VERSION 5.7 ;
  NOWIREEXTENSIONATPIN ON ;
  DIVIDERCHAR "/" ;
  BUSBITCHARS "[]" ;
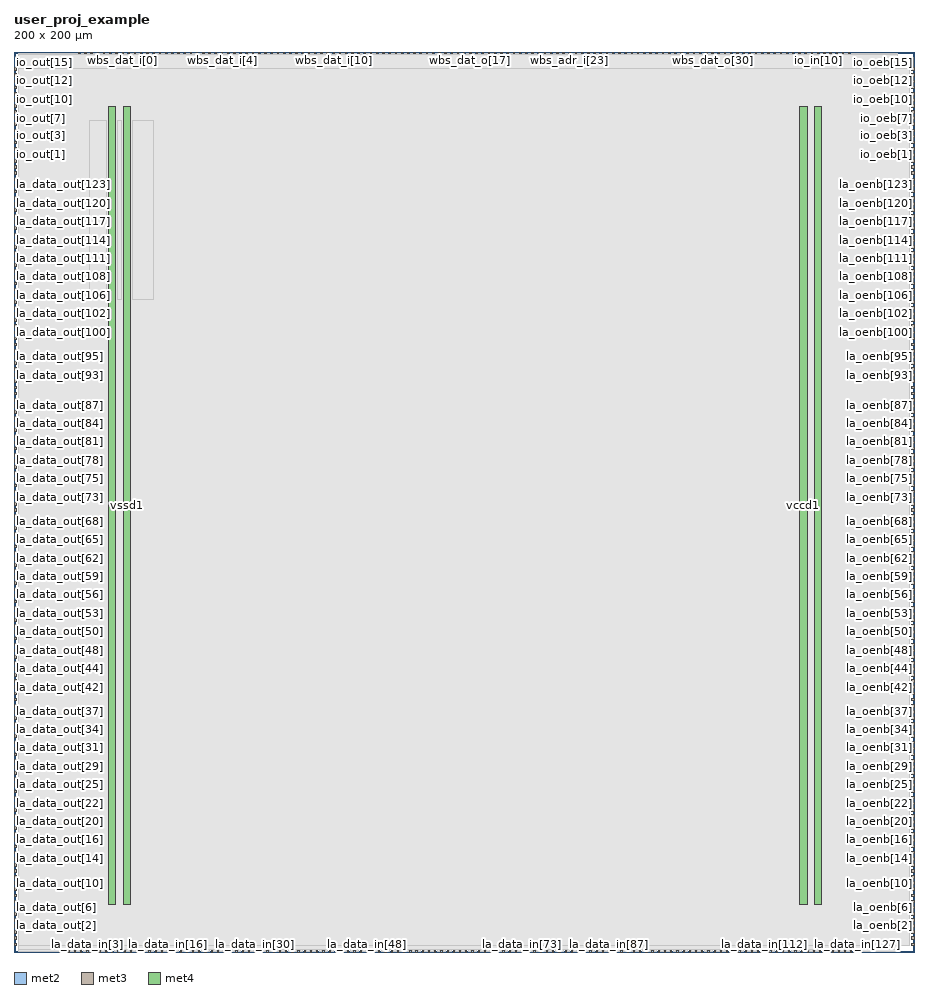
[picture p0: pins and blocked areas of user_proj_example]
MACRO user_proj_example
  CLASS BLOCK ;
  FOREIGN user_proj_example ;
  ORIGIN 0.000 0.000 ;
  SIZE 200.000 BY 200.000 ;
  PIN io_in[0]
    DIRECTION INPUT ;
    USE SIGNAL ;
    PORT
      LAYER met2 ;
        RECT 164.770 199.720 165.050 200.000 ;
    END
  END io_in[0]
  PIN io_in[10]
    DIRECTION INPUT ;
    USE SIGNAL ;
    PORT
      LAYER met2 ;
        RECT 178.570 199.720 178.850 200.000 ;
    END
  END io_in[10]
  PIN io_in[11]
    DIRECTION INPUT ;
    USE SIGNAL ;
    PORT
      LAYER met2 ;
        RECT 179.950 199.720 180.230 200.000 ;
    END
  END io_in[11]
  PIN io_in[12]
    DIRECTION INPUT ;
    USE SIGNAL ;
    PORT
      LAYER met2 ;
        RECT 181.330 199.720 181.610 200.000 ;
    END
  END io_in[12]
  PIN io_in[13]
    DIRECTION INPUT ;
    USE SIGNAL ;
    PORT
      LAYER met2 ;
        RECT 182.710 199.720 182.990 200.000 ;
    END
  END io_in[13]
  PIN io_in[14]
    DIRECTION INPUT ;
    USE SIGNAL ;
    PORT
      LAYER met2 ;
        RECT 184.090 199.720 184.370 200.000 ;
    END
  END io_in[14]
  PIN io_in[15]
    DIRECTION INPUT ;
    USE SIGNAL ;
    PORT
      LAYER met2 ;
        RECT 185.470 199.720 185.750 200.000 ;
    END
  END io_in[15]
  PIN io_in[1]
    DIRECTION INPUT ;
    USE SIGNAL ;
    PORT
      LAYER met2 ;
        RECT 166.150 199.720 166.430 200.000 ;
    END
  END io_in[1]
  PIN io_in[2]
    DIRECTION INPUT ;
    USE SIGNAL ;
    PORT
      LAYER met2 ;
        RECT 167.530 199.720 167.810 200.000 ;
    END
  END io_in[2]
  PIN io_in[3]
    DIRECTION INPUT ;
    USE SIGNAL ;
    PORT
      LAYER met2 ;
        RECT 168.910 199.720 169.190 200.000 ;
    END
  END io_in[3]
  PIN io_in[4]
    DIRECTION INPUT ;
    USE SIGNAL ;
    PORT
      LAYER met2 ;
        RECT 170.290 199.720 170.570 200.000 ;
    END
  END io_in[4]
  PIN io_in[5]
    DIRECTION INPUT ;
    USE SIGNAL ;
    PORT
      LAYER met2 ;
        RECT 171.670 199.720 171.950 200.000 ;
    END
  END io_in[5]
  PIN io_in[6]
    DIRECTION INPUT ;
    USE SIGNAL ;
    PORT
      LAYER met2 ;
        RECT 173.050 199.720 173.330 200.000 ;
    END
  END io_in[6]
  PIN io_in[7]
    DIRECTION INPUT ;
    USE SIGNAL ;
    PORT
      LAYER met2 ;
        RECT 174.430 199.720 174.710 200.000 ;
    END
  END io_in[7]
  PIN io_in[8]
    DIRECTION INPUT ;
    USE SIGNAL ;
    PORT
      LAYER met2 ;
        RECT 175.810 199.720 176.090 200.000 ;
    END
  END io_in[8]
  PIN io_in[9]
    DIRECTION INPUT ;
    USE SIGNAL ;
    PORT
      LAYER met2 ;
        RECT 177.190 199.720 177.470 200.000 ;
    END
  END io_in[9]
  PIN io_oeb[0]
    DIRECTION OUTPUT ;
    USE SIGNAL ;
    ANTENNADIFFAREA 2.673000 ;
    PORT
      LAYER met3 ;
        RECT 199.400 175.480 200.000 176.080 ;
    END
  END io_oeb[0]
  PIN io_oeb[10]
    DIRECTION OUTPUT ;
    USE SIGNAL ;
    ANTENNADIFFAREA 2.673000 ;
    PORT
      LAYER met3 ;
        RECT 199.400 189.080 200.000 189.680 ;
    END
  END io_oeb[10]
  PIN io_oeb[11]
    DIRECTION OUTPUT ;
    USE SIGNAL ;
    ANTENNADIFFAREA 2.673000 ;
    PORT
      LAYER met3 ;
        RECT 199.400 190.440 200.000 191.040 ;
    END
  END io_oeb[11]
  PIN io_oeb[12]
    DIRECTION OUTPUT ;
    USE SIGNAL ;
    ANTENNADIFFAREA 2.673000 ;
    PORT
      LAYER met3 ;
        RECT 199.400 191.800 200.000 192.400 ;
    END
  END io_oeb[12]
  PIN io_oeb[13]
    DIRECTION OUTPUT ;
    USE SIGNAL ;
    ANTENNADIFFAREA 2.673000 ;
    PORT
      LAYER met3 ;
        RECT 199.400 193.160 200.000 193.760 ;
    END
  END io_oeb[13]
  PIN io_oeb[14]
    DIRECTION OUTPUT ;
    USE SIGNAL ;
    ANTENNADIFFAREA 2.673000 ;
    PORT
      LAYER met3 ;
        RECT 199.400 194.520 200.000 195.120 ;
    END
  END io_oeb[14]
  PIN io_oeb[15]
    DIRECTION OUTPUT ;
    USE SIGNAL ;
    ANTENNADIFFAREA 2.673000 ;
    PORT
      LAYER met3 ;
        RECT 199.400 195.880 200.000 196.480 ;
    END
  END io_oeb[15]
  PIN io_oeb[1]
    DIRECTION OUTPUT ;
    USE SIGNAL ;
    ANTENNADIFFAREA 2.673000 ;
    PORT
      LAYER met3 ;
        RECT 199.400 176.840 200.000 177.440 ;
    END
  END io_oeb[1]
  PIN io_oeb[2]
    DIRECTION OUTPUT ;
    USE SIGNAL ;
    ANTENNADIFFAREA 2.673000 ;
    PORT
      LAYER met3 ;
        RECT 199.400 178.200 200.000 178.800 ;
    END
  END io_oeb[2]
  PIN io_oeb[3]
    DIRECTION OUTPUT ;
    USE SIGNAL ;
    ANTENNADIFFAREA 2.673000 ;
    PORT
      LAYER met3 ;
        RECT 199.400 179.560 200.000 180.160 ;
    END
  END io_oeb[3]
  PIN io_oeb[4]
    DIRECTION OUTPUT ;
    USE SIGNAL ;
    ANTENNADIFFAREA 2.673000 ;
    PORT
      LAYER met3 ;
        RECT 199.400 180.920 200.000 181.520 ;
    END
  END io_oeb[4]
  PIN io_oeb[5]
    DIRECTION OUTPUT ;
    USE SIGNAL ;
    ANTENNADIFFAREA 2.673000 ;
    PORT
      LAYER met3 ;
        RECT 199.400 182.280 200.000 182.880 ;
    END
  END io_oeb[5]
  PIN io_oeb[6]
    DIRECTION OUTPUT ;
    USE SIGNAL ;
    ANTENNADIFFAREA 2.673000 ;
    PORT
      LAYER met3 ;
        RECT 199.400 183.640 200.000 184.240 ;
    END
  END io_oeb[6]
  PIN io_oeb[7]
    DIRECTION OUTPUT ;
    USE SIGNAL ;
    ANTENNADIFFAREA 2.673000 ;
    PORT
      LAYER met3 ;
        RECT 199.400 185.000 200.000 185.600 ;
    END
  END io_oeb[7]
  PIN io_oeb[8]
    DIRECTION OUTPUT ;
    USE SIGNAL ;
    ANTENNADIFFAREA 2.673000 ;
    PORT
      LAYER met3 ;
        RECT 199.400 186.360 200.000 186.960 ;
    END
  END io_oeb[8]
  PIN io_oeb[9]
    DIRECTION OUTPUT ;
    USE SIGNAL ;
    ANTENNADIFFAREA 2.673000 ;
    PORT
      LAYER met3 ;
        RECT 199.400 187.720 200.000 188.320 ;
    END
  END io_oeb[9]
  PIN io_out[0]
    DIRECTION OUTPUT ;
    USE SIGNAL ;
    ANTENNADIFFAREA 2.673000 ;
    PORT
      LAYER met3 ;
        RECT 0.000 175.480 0.600 176.080 ;
    END
  END io_out[0]
  PIN io_out[10]
    DIRECTION OUTPUT ;
    USE SIGNAL ;
    ANTENNADIFFAREA 2.673000 ;
    PORT
      LAYER met3 ;
        RECT 0.000 189.080 0.600 189.680 ;
    END
  END io_out[10]
  PIN io_out[11]
    DIRECTION OUTPUT ;
    USE SIGNAL ;
    ANTENNADIFFAREA 2.673000 ;
    PORT
      LAYER met3 ;
        RECT 0.000 190.440 0.600 191.040 ;
    END
  END io_out[11]
  PIN io_out[12]
    DIRECTION OUTPUT ;
    USE SIGNAL ;
    ANTENNADIFFAREA 2.673000 ;
    PORT
      LAYER met3 ;
        RECT 0.000 191.800 0.600 192.400 ;
    END
  END io_out[12]
  PIN io_out[13]
    DIRECTION OUTPUT ;
    USE SIGNAL ;
    ANTENNADIFFAREA 2.673000 ;
    PORT
      LAYER met3 ;
        RECT 0.000 193.160 0.600 193.760 ;
    END
  END io_out[13]
  PIN io_out[14]
    DIRECTION OUTPUT ;
    USE SIGNAL ;
    ANTENNADIFFAREA 2.673000 ;
    PORT
      LAYER met3 ;
        RECT 0.000 194.520 0.600 195.120 ;
    END
  END io_out[14]
  PIN io_out[15]
    DIRECTION OUTPUT ;
    USE SIGNAL ;
    ANTENNADIFFAREA 2.673000 ;
    PORT
      LAYER met3 ;
        RECT 0.000 195.880 0.600 196.480 ;
    END
  END io_out[15]
  PIN io_out[1]
    DIRECTION OUTPUT ;
    USE SIGNAL ;
    ANTENNADIFFAREA 2.673000 ;
    PORT
      LAYER met3 ;
        RECT 0.000 176.840 0.600 177.440 ;
    END
  END io_out[1]
  PIN io_out[2]
    DIRECTION OUTPUT ;
    USE SIGNAL ;
    ANTENNADIFFAREA 2.673000 ;
    PORT
      LAYER met3 ;
        RECT 0.000 178.200 0.600 178.800 ;
    END
  END io_out[2]
  PIN io_out[3]
    DIRECTION OUTPUT ;
    USE SIGNAL ;
    ANTENNADIFFAREA 2.673000 ;
    PORT
      LAYER met3 ;
        RECT 0.000 179.560 0.600 180.160 ;
    END
  END io_out[3]
  PIN io_out[4]
    DIRECTION OUTPUT ;
    USE SIGNAL ;
    ANTENNADIFFAREA 2.673000 ;
    PORT
      LAYER met3 ;
        RECT 0.000 180.920 0.600 181.520 ;
    END
  END io_out[4]
  PIN io_out[5]
    DIRECTION OUTPUT ;
    USE SIGNAL ;
    ANTENNADIFFAREA 2.673000 ;
    PORT
      LAYER met3 ;
        RECT 0.000 182.280 0.600 182.880 ;
    END
  END io_out[5]
  PIN io_out[6]
    DIRECTION OUTPUT ;
    USE SIGNAL ;
    ANTENNADIFFAREA 2.673000 ;
    PORT
      LAYER met3 ;
        RECT 0.000 183.640 0.600 184.240 ;
    END
  END io_out[6]
  PIN io_out[7]
    DIRECTION OUTPUT ;
    USE SIGNAL ;
    ANTENNADIFFAREA 2.673000 ;
    PORT
      LAYER met3 ;
        RECT 0.000 185.000 0.600 185.600 ;
    END
  END io_out[7]
  PIN io_out[8]
    DIRECTION OUTPUT ;
    USE SIGNAL ;
    ANTENNADIFFAREA 2.673000 ;
    PORT
      LAYER met3 ;
        RECT 0.000 186.360 0.600 186.960 ;
    END
  END io_out[8]
  PIN io_out[9]
    DIRECTION OUTPUT ;
    USE SIGNAL ;
    ANTENNADIFFAREA 2.673000 ;
    PORT
      LAYER met3 ;
        RECT 0.000 187.720 0.600 188.320 ;
    END
  END io_out[9]
  PIN irq[0]
    DIRECTION OUTPUT ;
    USE SIGNAL ;
    PORT
      LAYER met2 ;
        RECT 160.630 199.720 160.910 200.000 ;
    END
  END irq[0]
  PIN irq[1]
    DIRECTION OUTPUT ;
    USE SIGNAL ;
    PORT
      LAYER met2 ;
        RECT 162.010 199.720 162.290 200.000 ;
    END
  END irq[1]
  PIN irq[2]
    DIRECTION OUTPUT ;
    USE SIGNAL ;
    PORT
      LAYER met2 ;
        RECT 163.390 199.720 163.670 200.000 ;
    END
  END irq[2]
  PIN la_data_in[0]
    DIRECTION INPUT ;
    USE SIGNAL ;
    PORT
      LAYER met2 ;
        RECT 12.050 0.000 12.330 0.280 ;
    END
  END la_data_in[0]
  PIN la_data_in[100]
    DIRECTION INPUT ;
    USE SIGNAL ;
    PORT
      LAYER met2 ;
        RECT 150.050 0.000 150.330 0.280 ;
    END
  END la_data_in[100]
  PIN la_data_in[101]
    DIRECTION INPUT ;
    USE SIGNAL ;
    PORT
      LAYER met2 ;
        RECT 151.430 0.000 151.710 0.280 ;
    END
  END la_data_in[101]
  PIN la_data_in[102]
    DIRECTION INPUT ;
    USE SIGNAL ;
    PORT
      LAYER met2 ;
        RECT 152.810 0.000 153.090 0.280 ;
    END
  END la_data_in[102]
  PIN la_data_in[103]
    DIRECTION INPUT ;
    USE SIGNAL ;
    PORT
      LAYER met2 ;
        RECT 154.190 0.000 154.470 0.280 ;
    END
  END la_data_in[103]
  PIN la_data_in[104]
    DIRECTION INPUT ;
    USE SIGNAL ;
    PORT
      LAYER met2 ;
        RECT 155.570 0.000 155.850 0.280 ;
    END
  END la_data_in[104]
  PIN la_data_in[105]
    DIRECTION INPUT ;
    USE SIGNAL ;
    PORT
      LAYER met2 ;
        RECT 156.950 0.000 157.230 0.280 ;
    END
  END la_data_in[105]
  PIN la_data_in[106]
    DIRECTION INPUT ;
    USE SIGNAL ;
    PORT
      LAYER met2 ;
        RECT 158.330 0.000 158.610 0.280 ;
    END
  END la_data_in[106]
  PIN la_data_in[107]
    DIRECTION INPUT ;
    USE SIGNAL ;
    PORT
      LAYER met2 ;
        RECT 159.710 0.000 159.990 0.280 ;
    END
  END la_data_in[107]
  PIN la_data_in[108]
    DIRECTION INPUT ;
    USE SIGNAL ;
    PORT
      LAYER met2 ;
        RECT 161.090 0.000 161.370 0.280 ;
    END
  END la_data_in[108]
  PIN la_data_in[109]
    DIRECTION INPUT ;
    USE SIGNAL ;
    PORT
      LAYER met2 ;
        RECT 162.470 0.000 162.750 0.280 ;
    END
  END la_data_in[109]
  PIN la_data_in[10]
    DIRECTION INPUT ;
    USE SIGNAL ;
    PORT
      LAYER met2 ;
        RECT 25.850 0.000 26.130 0.280 ;
    END
  END la_data_in[10]
  PIN la_data_in[110]
    DIRECTION INPUT ;
    USE SIGNAL ;
    PORT
      LAYER met2 ;
        RECT 163.850 0.000 164.130 0.280 ;
    END
  END la_data_in[110]
  PIN la_data_in[111]
    DIRECTION INPUT ;
    USE SIGNAL ;
    PORT
      LAYER met2 ;
        RECT 165.230 0.000 165.510 0.280 ;
    END
  END la_data_in[111]
  PIN la_data_in[112]
    DIRECTION INPUT ;
    USE SIGNAL ;
    PORT
      LAYER met2 ;
        RECT 166.610 0.000 166.890 0.280 ;
    END
  END la_data_in[112]
  PIN la_data_in[113]
    DIRECTION INPUT ;
    USE SIGNAL ;
    PORT
      LAYER met2 ;
        RECT 167.990 0.000 168.270 0.280 ;
    END
  END la_data_in[113]
  PIN la_data_in[114]
    DIRECTION INPUT ;
    USE SIGNAL ;
    PORT
      LAYER met2 ;
        RECT 169.370 0.000 169.650 0.280 ;
    END
  END la_data_in[114]
  PIN la_data_in[115]
    DIRECTION INPUT ;
    USE SIGNAL ;
    PORT
      LAYER met2 ;
        RECT 170.750 0.000 171.030 0.280 ;
    END
  END la_data_in[115]
  PIN la_data_in[116]
    DIRECTION INPUT ;
    USE SIGNAL ;
    PORT
      LAYER met2 ;
        RECT 172.130 0.000 172.410 0.280 ;
    END
  END la_data_in[116]
  PIN la_data_in[117]
    DIRECTION INPUT ;
    USE SIGNAL ;
    PORT
      LAYER met2 ;
        RECT 173.510 0.000 173.790 0.280 ;
    END
  END la_data_in[117]
  PIN la_data_in[118]
    DIRECTION INPUT ;
    USE SIGNAL ;
    PORT
      LAYER met2 ;
        RECT 174.890 0.000 175.170 0.280 ;
    END
  END la_data_in[118]
  PIN la_data_in[119]
    DIRECTION INPUT ;
    USE SIGNAL ;
    PORT
      LAYER met2 ;
        RECT 176.270 0.000 176.550 0.280 ;
    END
  END la_data_in[119]
  PIN la_data_in[11]
    DIRECTION INPUT ;
    USE SIGNAL ;
    PORT
      LAYER met2 ;
        RECT 27.230 0.000 27.510 0.280 ;
    END
  END la_data_in[11]
  PIN la_data_in[120]
    DIRECTION INPUT ;
    USE SIGNAL ;
    PORT
      LAYER met2 ;
        RECT 177.650 0.000 177.930 0.280 ;
    END
  END la_data_in[120]
  PIN la_data_in[121]
    DIRECTION INPUT ;
    USE SIGNAL ;
    PORT
      LAYER met2 ;
        RECT 179.030 0.000 179.310 0.280 ;
    END
  END la_data_in[121]
  PIN la_data_in[122]
    DIRECTION INPUT ;
    USE SIGNAL ;
    PORT
      LAYER met2 ;
        RECT 180.410 0.000 180.690 0.280 ;
    END
  END la_data_in[122]
  PIN la_data_in[123]
    DIRECTION INPUT ;
    USE SIGNAL ;
    PORT
      LAYER met2 ;
        RECT 181.790 0.000 182.070 0.280 ;
    END
  END la_data_in[123]
  PIN la_data_in[124]
    DIRECTION INPUT ;
    USE SIGNAL ;
    PORT
      LAYER met2 ;
        RECT 183.170 0.000 183.450 0.280 ;
    END
  END la_data_in[124]
  PIN la_data_in[125]
    DIRECTION INPUT ;
    USE SIGNAL ;
    PORT
      LAYER met2 ;
        RECT 184.550 0.000 184.830 0.280 ;
    END
  END la_data_in[125]
  PIN la_data_in[126]
    DIRECTION INPUT ;
    USE SIGNAL ;
    PORT
      LAYER met2 ;
        RECT 185.930 0.000 186.210 0.280 ;
    END
  END la_data_in[126]
  PIN la_data_in[127]
    DIRECTION INPUT ;
    USE SIGNAL ;
    PORT
      LAYER met2 ;
        RECT 187.310 0.000 187.590 0.280 ;
    END
  END la_data_in[127]
  PIN la_data_in[12]
    DIRECTION INPUT ;
    USE SIGNAL ;
    PORT
      LAYER met2 ;
        RECT 28.610 0.000 28.890 0.280 ;
    END
  END la_data_in[12]
  PIN la_data_in[13]
    DIRECTION INPUT ;
    USE SIGNAL ;
    PORT
      LAYER met2 ;
        RECT 29.990 0.000 30.270 0.280 ;
    END
  END la_data_in[13]
  PIN la_data_in[14]
    DIRECTION INPUT ;
    USE SIGNAL ;
    PORT
      LAYER met2 ;
        RECT 31.370 0.000 31.650 0.280 ;
    END
  END la_data_in[14]
  PIN la_data_in[15]
    DIRECTION INPUT ;
    USE SIGNAL ;
    PORT
      LAYER met2 ;
        RECT 32.750 0.000 33.030 0.280 ;
    END
  END la_data_in[15]
  PIN la_data_in[16]
    DIRECTION INPUT ;
    USE SIGNAL ;
    PORT
      LAYER met2 ;
        RECT 34.130 0.000 34.410 0.280 ;
    END
  END la_data_in[16]
  PIN la_data_in[17]
    DIRECTION INPUT ;
    USE SIGNAL ;
    PORT
      LAYER met2 ;
        RECT 35.510 0.000 35.790 0.280 ;
    END
  END la_data_in[17]
  PIN la_data_in[18]
    DIRECTION INPUT ;
    USE SIGNAL ;
    PORT
      LAYER met2 ;
        RECT 36.890 0.000 37.170 0.280 ;
    END
  END la_data_in[18]
  PIN la_data_in[19]
    DIRECTION INPUT ;
    USE SIGNAL ;
    PORT
      LAYER met2 ;
        RECT 38.270 0.000 38.550 0.280 ;
    END
  END la_data_in[19]
  PIN la_data_in[1]
    DIRECTION INPUT ;
    USE SIGNAL ;
    PORT
      LAYER met2 ;
        RECT 13.430 0.000 13.710 0.280 ;
    END
  END la_data_in[1]
  PIN la_data_in[20]
    DIRECTION INPUT ;
    USE SIGNAL ;
    PORT
      LAYER met2 ;
        RECT 39.650 0.000 39.930 0.280 ;
    END
  END la_data_in[20]
  PIN la_data_in[21]
    DIRECTION INPUT ;
    USE SIGNAL ;
    PORT
      LAYER met2 ;
        RECT 41.030 0.000 41.310 0.280 ;
    END
  END la_data_in[21]
  PIN la_data_in[22]
    DIRECTION INPUT ;
    USE SIGNAL ;
    PORT
      LAYER met2 ;
        RECT 42.410 0.000 42.690 0.280 ;
    END
  END la_data_in[22]
  PIN la_data_in[23]
    DIRECTION INPUT ;
    USE SIGNAL ;
    PORT
      LAYER met2 ;
        RECT 43.790 0.000 44.070 0.280 ;
    END
  END la_data_in[23]
  PIN la_data_in[24]
    DIRECTION INPUT ;
    USE SIGNAL ;
    PORT
      LAYER met2 ;
        RECT 45.170 0.000 45.450 0.280 ;
    END
  END la_data_in[24]
  PIN la_data_in[25]
    DIRECTION INPUT ;
    USE SIGNAL ;
    PORT
      LAYER met2 ;
        RECT 46.550 0.000 46.830 0.280 ;
    END
  END la_data_in[25]
  PIN la_data_in[26]
    DIRECTION INPUT ;
    USE SIGNAL ;
    PORT
      LAYER met2 ;
        RECT 47.930 0.000 48.210 0.280 ;
    END
  END la_data_in[26]
  PIN la_data_in[27]
    DIRECTION INPUT ;
    USE SIGNAL ;
    PORT
      LAYER met2 ;
        RECT 49.310 0.000 49.590 0.280 ;
    END
  END la_data_in[27]
  PIN la_data_in[28]
    DIRECTION INPUT ;
    USE SIGNAL ;
    PORT
      LAYER met2 ;
        RECT 50.690 0.000 50.970 0.280 ;
    END
  END la_data_in[28]
  PIN la_data_in[29]
    DIRECTION INPUT ;
    USE SIGNAL ;
    PORT
      LAYER met2 ;
        RECT 52.070 0.000 52.350 0.280 ;
    END
  END la_data_in[29]
  PIN la_data_in[2]
    DIRECTION INPUT ;
    USE SIGNAL ;
    PORT
      LAYER met2 ;
        RECT 14.810 0.000 15.090 0.280 ;
    END
  END la_data_in[2]
  PIN la_data_in[30]
    DIRECTION INPUT ;
    USE SIGNAL ;
    PORT
      LAYER met2 ;
        RECT 53.450 0.000 53.730 0.280 ;
    END
  END la_data_in[30]
  PIN la_data_in[31]
    DIRECTION INPUT ;
    USE SIGNAL ;
    PORT
      LAYER met2 ;
        RECT 54.830 0.000 55.110 0.280 ;
    END
  END la_data_in[31]
  PIN la_data_in[32]
    DIRECTION INPUT ;
    USE SIGNAL ;
    PORT
      LAYER met2 ;
        RECT 56.210 0.000 56.490 0.280 ;
    END
  END la_data_in[32]
  PIN la_data_in[33]
    DIRECTION INPUT ;
    USE SIGNAL ;
    PORT
      LAYER met2 ;
        RECT 57.590 0.000 57.870 0.280 ;
    END
  END la_data_in[33]
  PIN la_data_in[34]
    DIRECTION INPUT ;
    USE SIGNAL ;
    PORT
      LAYER met2 ;
        RECT 58.970 0.000 59.250 0.280 ;
    END
  END la_data_in[34]
  PIN la_data_in[35]
    DIRECTION INPUT ;
    USE SIGNAL ;
    PORT
      LAYER met2 ;
        RECT 60.350 0.000 60.630 0.280 ;
    END
  END la_data_in[35]
  PIN la_data_in[36]
    DIRECTION INPUT ;
    USE SIGNAL ;
    PORT
      LAYER met2 ;
        RECT 61.730 0.000 62.010 0.280 ;
    END
  END la_data_in[36]
  PIN la_data_in[37]
    DIRECTION INPUT ;
    USE SIGNAL ;
    PORT
      LAYER met2 ;
        RECT 63.110 0.000 63.390 0.280 ;
    END
  END la_data_in[37]
  PIN la_data_in[38]
    DIRECTION INPUT ;
    USE SIGNAL ;
    PORT
      LAYER met2 ;
        RECT 64.490 0.000 64.770 0.280 ;
    END
  END la_data_in[38]
  PIN la_data_in[39]
    DIRECTION INPUT ;
    USE SIGNAL ;
    PORT
      LAYER met2 ;
        RECT 65.870 0.000 66.150 0.280 ;
    END
  END la_data_in[39]
  PIN la_data_in[3]
    DIRECTION INPUT ;
    USE SIGNAL ;
    PORT
      LAYER met2 ;
        RECT 16.190 0.000 16.470 0.280 ;
    END
  END la_data_in[3]
  PIN la_data_in[40]
    DIRECTION INPUT ;
    USE SIGNAL ;
    PORT
      LAYER met2 ;
        RECT 67.250 0.000 67.530 0.280 ;
    END
  END la_data_in[40]
  PIN la_data_in[41]
    DIRECTION INPUT ;
    USE SIGNAL ;
    PORT
      LAYER met2 ;
        RECT 68.630 0.000 68.910 0.280 ;
    END
  END la_data_in[41]
  PIN la_data_in[42]
    DIRECTION INPUT ;
    USE SIGNAL ;
    PORT
      LAYER met2 ;
        RECT 70.010 0.000 70.290 0.280 ;
    END
  END la_data_in[42]
  PIN la_data_in[43]
    DIRECTION INPUT ;
    USE SIGNAL ;
    PORT
      LAYER met2 ;
        RECT 71.390 0.000 71.670 0.280 ;
    END
  END la_data_in[43]
  PIN la_data_in[44]
    DIRECTION INPUT ;
    USE SIGNAL ;
    PORT
      LAYER met2 ;
        RECT 72.770 0.000 73.050 0.280 ;
    END
  END la_data_in[44]
  PIN la_data_in[45]
    DIRECTION INPUT ;
    USE SIGNAL ;
    PORT
      LAYER met2 ;
        RECT 74.150 0.000 74.430 0.280 ;
    END
  END la_data_in[45]
  PIN la_data_in[46]
    DIRECTION INPUT ;
    USE SIGNAL ;
    PORT
      LAYER met2 ;
        RECT 75.530 0.000 75.810 0.280 ;
    END
  END la_data_in[46]
  PIN la_data_in[47]
    DIRECTION INPUT ;
    USE SIGNAL ;
    PORT
      LAYER met2 ;
        RECT 76.910 0.000 77.190 0.280 ;
    END
  END la_data_in[47]
  PIN la_data_in[48]
    DIRECTION INPUT ;
    USE SIGNAL ;
    ANTENNAGATEAREA 0.560700 ;
    ANTENNADIFFAREA 0.434700 ;
    PORT
      LAYER met2 ;
        RECT 78.290 0.000 78.570 0.280 ;
    END
  END la_data_in[48]
  PIN la_data_in[49]
    DIRECTION INPUT ;
    USE SIGNAL ;
    ANTENNAGATEAREA 0.560700 ;
    ANTENNADIFFAREA 0.434700 ;
    PORT
      LAYER met2 ;
        RECT 79.670 0.000 79.950 0.280 ;
    END
  END la_data_in[49]
  PIN la_data_in[4]
    DIRECTION INPUT ;
    USE SIGNAL ;
    PORT
      LAYER met2 ;
        RECT 17.570 0.000 17.850 0.280 ;
    END
  END la_data_in[4]
  PIN la_data_in[50]
    DIRECTION INPUT ;
    USE SIGNAL ;
    ANTENNAGATEAREA 0.560700 ;
    ANTENNADIFFAREA 0.434700 ;
    PORT
      LAYER met2 ;
        RECT 81.050 0.000 81.330 0.280 ;
    END
  END la_data_in[50]
  PIN la_data_in[51]
    DIRECTION INPUT ;
    USE SIGNAL ;
    ANTENNAGATEAREA 0.560700 ;
    ANTENNADIFFAREA 0.434700 ;
    PORT
      LAYER met2 ;
        RECT 82.430 0.000 82.710 0.280 ;
    END
  END la_data_in[51]
  PIN la_data_in[52]
    DIRECTION INPUT ;
    USE SIGNAL ;
    ANTENNAGATEAREA 0.560700 ;
    ANTENNADIFFAREA 0.434700 ;
    PORT
      LAYER met2 ;
        RECT 83.810 0.000 84.090 0.280 ;
    END
  END la_data_in[52]
  PIN la_data_in[53]
    DIRECTION INPUT ;
    USE SIGNAL ;
    ANTENNAGATEAREA 0.560700 ;
    ANTENNADIFFAREA 0.434700 ;
    PORT
      LAYER met2 ;
        RECT 85.190 0.000 85.470 0.280 ;
    END
  END la_data_in[53]
  PIN la_data_in[54]
    DIRECTION INPUT ;
    USE SIGNAL ;
    ANTENNAGATEAREA 0.560700 ;
    ANTENNADIFFAREA 0.434700 ;
    PORT
      LAYER met2 ;
        RECT 86.570 0.000 86.850 0.280 ;
    END
  END la_data_in[54]
  PIN la_data_in[55]
    DIRECTION INPUT ;
    USE SIGNAL ;
    ANTENNAGATEAREA 0.560700 ;
    ANTENNADIFFAREA 0.434700 ;
    PORT
      LAYER met2 ;
        RECT 87.950 0.000 88.230 0.280 ;
    END
  END la_data_in[55]
  PIN la_data_in[56]
    DIRECTION INPUT ;
    USE SIGNAL ;
    ANTENNAGATEAREA 0.560700 ;
    ANTENNADIFFAREA 0.434700 ;
    PORT
      LAYER met2 ;
        RECT 89.330 0.000 89.610 0.280 ;
    END
  END la_data_in[56]
  PIN la_data_in[57]
    DIRECTION INPUT ;
    USE SIGNAL ;
    ANTENNAGATEAREA 0.560700 ;
    ANTENNADIFFAREA 0.434700 ;
    PORT
      LAYER met2 ;
        RECT 90.710 0.000 90.990 0.280 ;
    END
  END la_data_in[57]
  PIN la_data_in[58]
    DIRECTION INPUT ;
    USE SIGNAL ;
    ANTENNAGATEAREA 0.560700 ;
    ANTENNADIFFAREA 0.434700 ;
    PORT
      LAYER met2 ;
        RECT 92.090 0.000 92.370 0.280 ;
    END
  END la_data_in[58]
  PIN la_data_in[59]
    DIRECTION INPUT ;
    USE SIGNAL ;
    ANTENNAGATEAREA 0.560700 ;
    ANTENNADIFFAREA 0.434700 ;
    PORT
      LAYER met2 ;
        RECT 93.470 0.000 93.750 0.280 ;
    END
  END la_data_in[59]
  PIN la_data_in[5]
    DIRECTION INPUT ;
    USE SIGNAL ;
    PORT
      LAYER met2 ;
        RECT 18.950 0.000 19.230 0.280 ;
    END
  END la_data_in[5]
  PIN la_data_in[60]
    DIRECTION INPUT ;
    USE SIGNAL ;
    ANTENNAGATEAREA 0.560700 ;
    ANTENNADIFFAREA 0.434700 ;
    PORT
      LAYER met2 ;
        RECT 94.850 0.000 95.130 0.280 ;
    END
  END la_data_in[60]
  PIN la_data_in[61]
    DIRECTION INPUT ;
    USE SIGNAL ;
    ANTENNAGATEAREA 0.560700 ;
    ANTENNADIFFAREA 0.434700 ;
    PORT
      LAYER met2 ;
        RECT 96.230 0.000 96.510 0.280 ;
    END
  END la_data_in[61]
  PIN la_data_in[62]
    DIRECTION INPUT ;
    USE SIGNAL ;
    ANTENNAGATEAREA 0.560700 ;
    ANTENNADIFFAREA 0.434700 ;
    PORT
      LAYER met2 ;
        RECT 97.610 0.000 97.890 0.280 ;
    END
  END la_data_in[62]
  PIN la_data_in[63]
    DIRECTION INPUT ;
    USE SIGNAL ;
    ANTENNAGATEAREA 0.560700 ;
    ANTENNADIFFAREA 0.434700 ;
    PORT
      LAYER met2 ;
        RECT 98.990 0.000 99.270 0.280 ;
    END
  END la_data_in[63]
  PIN la_data_in[64]
    DIRECTION INPUT ;
    USE SIGNAL ;
    ANTENNAGATEAREA 0.647700 ;
    ANTENNADIFFAREA 0.434700 ;
    PORT
      LAYER met2 ;
        RECT 100.370 0.000 100.650 0.280 ;
    END
  END la_data_in[64]
  PIN la_data_in[65]
    DIRECTION INPUT ;
    USE SIGNAL ;
    ANTENNAGATEAREA 0.560700 ;
    ANTENNADIFFAREA 0.434700 ;
    PORT
      LAYER met2 ;
        RECT 101.750 0.000 102.030 0.280 ;
    END
  END la_data_in[65]
  PIN la_data_in[66]
    DIRECTION INPUT ;
    USE SIGNAL ;
    PORT
      LAYER met2 ;
        RECT 103.130 0.000 103.410 0.280 ;
    END
  END la_data_in[66]
  PIN la_data_in[67]
    DIRECTION INPUT ;
    USE SIGNAL ;
    PORT
      LAYER met2 ;
        RECT 104.510 0.000 104.790 0.280 ;
    END
  END la_data_in[67]
  PIN la_data_in[68]
    DIRECTION INPUT ;
    USE SIGNAL ;
    PORT
      LAYER met2 ;
        RECT 105.890 0.000 106.170 0.280 ;
    END
  END la_data_in[68]
  PIN la_data_in[69]
    DIRECTION INPUT ;
    USE SIGNAL ;
    PORT
      LAYER met2 ;
        RECT 107.270 0.000 107.550 0.280 ;
    END
  END la_data_in[69]
  PIN la_data_in[6]
    DIRECTION INPUT ;
    USE SIGNAL ;
    PORT
      LAYER met2 ;
        RECT 20.330 0.000 20.610 0.280 ;
    END
  END la_data_in[6]
  PIN la_data_in[70]
    DIRECTION INPUT ;
    USE SIGNAL ;
    PORT
      LAYER met2 ;
        RECT 108.650 0.000 108.930 0.280 ;
    END
  END la_data_in[70]
  PIN la_data_in[71]
    DIRECTION INPUT ;
    USE SIGNAL ;
    PORT
      LAYER met2 ;
        RECT 110.030 0.000 110.310 0.280 ;
    END
  END la_data_in[71]
  PIN la_data_in[72]
    DIRECTION INPUT ;
    USE SIGNAL ;
    PORT
      LAYER met2 ;
        RECT 111.410 0.000 111.690 0.280 ;
    END
  END la_data_in[72]
  PIN la_data_in[73]
    DIRECTION INPUT ;
    USE SIGNAL ;
    PORT
      LAYER met2 ;
        RECT 112.790 0.000 113.070 0.280 ;
    END
  END la_data_in[73]
  PIN la_data_in[74]
    DIRECTION INPUT ;
    USE SIGNAL ;
    PORT
      LAYER met2 ;
        RECT 114.170 0.000 114.450 0.280 ;
    END
  END la_data_in[74]
  PIN la_data_in[75]
    DIRECTION INPUT ;
    USE SIGNAL ;
    PORT
      LAYER met2 ;
        RECT 115.550 0.000 115.830 0.280 ;
    END
  END la_data_in[75]
  PIN la_data_in[76]
    DIRECTION INPUT ;
    USE SIGNAL ;
    PORT
      LAYER met2 ;
        RECT 116.930 0.000 117.210 0.280 ;
    END
  END la_data_in[76]
  PIN la_data_in[77]
    DIRECTION INPUT ;
    USE SIGNAL ;
    PORT
      LAYER met2 ;
        RECT 118.310 0.000 118.590 0.280 ;
    END
  END la_data_in[77]
  PIN la_data_in[78]
    DIRECTION INPUT ;
    USE SIGNAL ;
    PORT
      LAYER met2 ;
        RECT 119.690 0.000 119.970 0.280 ;
    END
  END la_data_in[78]
  PIN la_data_in[79]
    DIRECTION INPUT ;
    USE SIGNAL ;
    PORT
      LAYER met2 ;
        RECT 121.070 0.000 121.350 0.280 ;
    END
  END la_data_in[79]
  PIN la_data_in[7]
    DIRECTION INPUT ;
    USE SIGNAL ;
    PORT
      LAYER met2 ;
        RECT 21.710 0.000 21.990 0.280 ;
    END
  END la_data_in[7]
  PIN la_data_in[80]
    DIRECTION INPUT ;
    USE SIGNAL ;
    PORT
      LAYER met2 ;
        RECT 122.450 0.000 122.730 0.280 ;
    END
  END la_data_in[80]
  PIN la_data_in[81]
    DIRECTION INPUT ;
    USE SIGNAL ;
    PORT
      LAYER met2 ;
        RECT 123.830 0.000 124.110 0.280 ;
    END
  END la_data_in[81]
  PIN la_data_in[82]
    DIRECTION INPUT ;
    USE SIGNAL ;
    PORT
      LAYER met2 ;
        RECT 125.210 0.000 125.490 0.280 ;
    END
  END la_data_in[82]
  PIN la_data_in[83]
    DIRECTION INPUT ;
    USE SIGNAL ;
    PORT
      LAYER met2 ;
        RECT 126.590 0.000 126.870 0.280 ;
    END
  END la_data_in[83]
  PIN la_data_in[84]
    DIRECTION INPUT ;
    USE SIGNAL ;
    PORT
      LAYER met2 ;
        RECT 127.970 0.000 128.250 0.280 ;
    END
  END la_data_in[84]
  PIN la_data_in[85]
    DIRECTION INPUT ;
    USE SIGNAL ;
    PORT
      LAYER met2 ;
        RECT 129.350 0.000 129.630 0.280 ;
    END
  END la_data_in[85]
  PIN la_data_in[86]
    DIRECTION INPUT ;
    USE SIGNAL ;
    PORT
      LAYER met2 ;
        RECT 130.730 0.000 131.010 0.280 ;
    END
  END la_data_in[86]
  PIN la_data_in[87]
    DIRECTION INPUT ;
    USE SIGNAL ;
    PORT
      LAYER met2 ;
        RECT 132.110 0.000 132.390 0.280 ;
    END
  END la_data_in[87]
  PIN la_data_in[88]
    DIRECTION INPUT ;
    USE SIGNAL ;
    PORT
      LAYER met2 ;
        RECT 133.490 0.000 133.770 0.280 ;
    END
  END la_data_in[88]
  PIN la_data_in[89]
    DIRECTION INPUT ;
    USE SIGNAL ;
    PORT
      LAYER met2 ;
        RECT 134.870 0.000 135.150 0.280 ;
    END
  END la_data_in[89]
  PIN la_data_in[8]
    DIRECTION INPUT ;
    USE SIGNAL ;
    PORT
      LAYER met2 ;
        RECT 23.090 0.000 23.370 0.280 ;
    END
  END la_data_in[8]
  PIN la_data_in[90]
    DIRECTION INPUT ;
    USE SIGNAL ;
    PORT
      LAYER met2 ;
        RECT 136.250 0.000 136.530 0.280 ;
    END
  END la_data_in[90]
  PIN la_data_in[91]
    DIRECTION INPUT ;
    USE SIGNAL ;
    PORT
      LAYER met2 ;
        RECT 137.630 0.000 137.910 0.280 ;
    END
  END la_data_in[91]
  PIN la_data_in[92]
    DIRECTION INPUT ;
    USE SIGNAL ;
    PORT
      LAYER met2 ;
        RECT 139.010 0.000 139.290 0.280 ;
    END
  END la_data_in[92]
  PIN la_data_in[93]
    DIRECTION INPUT ;
    USE SIGNAL ;
    PORT
      LAYER met2 ;
        RECT 140.390 0.000 140.670 0.280 ;
    END
  END la_data_in[93]
  PIN la_data_in[94]
    DIRECTION INPUT ;
    USE SIGNAL ;
    PORT
      LAYER met2 ;
        RECT 141.770 0.000 142.050 0.280 ;
    END
  END la_data_in[94]
  PIN la_data_in[95]
    DIRECTION INPUT ;
    USE SIGNAL ;
    PORT
      LAYER met2 ;
        RECT 143.150 0.000 143.430 0.280 ;
    END
  END la_data_in[95]
  PIN la_data_in[96]
    DIRECTION INPUT ;
    USE SIGNAL ;
    PORT
      LAYER met2 ;
        RECT 144.530 0.000 144.810 0.280 ;
    END
  END la_data_in[96]
  PIN la_data_in[97]
    DIRECTION INPUT ;
    USE SIGNAL ;
    PORT
      LAYER met2 ;
        RECT 145.910 0.000 146.190 0.280 ;
    END
  END la_data_in[97]
  PIN la_data_in[98]
    DIRECTION INPUT ;
    USE SIGNAL ;
    PORT
      LAYER met2 ;
        RECT 147.290 0.000 147.570 0.280 ;
    END
  END la_data_in[98]
  PIN la_data_in[99]
    DIRECTION INPUT ;
    USE SIGNAL ;
    PORT
      LAYER met2 ;
        RECT 148.670 0.000 148.950 0.280 ;
    END
  END la_data_in[99]
  PIN la_data_in[9]
    DIRECTION INPUT ;
    USE SIGNAL ;
    PORT
      LAYER met2 ;
        RECT 24.470 0.000 24.750 0.280 ;
    END
  END la_data_in[9]
  PIN la_data_out[0]
    DIRECTION OUTPUT ;
    USE SIGNAL ;
    ANTENNADIFFAREA 2.673000 ;
    PORT
      LAYER met3 ;
        RECT 0.000 1.400 0.600 2.000 ;
    END
  END la_data_out[0]
  PIN la_data_out[100]
    DIRECTION OUTPUT ;
    USE SIGNAL ;
    PORT
      LAYER met3 ;
        RECT 0.000 137.400 0.600 138.000 ;
    END
  END la_data_out[100]
  PIN la_data_out[101]
    DIRECTION OUTPUT ;
    USE SIGNAL ;
    PORT
      LAYER met3 ;
        RECT 0.000 138.760 0.600 139.360 ;
    END
  END la_data_out[101]
  PIN la_data_out[102]
    DIRECTION OUTPUT ;
    USE SIGNAL ;
    PORT
      LAYER met3 ;
        RECT 0.000 140.120 0.600 140.720 ;
    END
  END la_data_out[102]
  PIN la_data_out[103]
    DIRECTION OUTPUT ;
    USE SIGNAL ;
    PORT
      LAYER met3 ;
        RECT 0.000 141.480 0.600 142.080 ;
    END
  END la_data_out[103]
  PIN la_data_out[104]
    DIRECTION OUTPUT ;
    USE SIGNAL ;
    PORT
      LAYER met3 ;
        RECT 0.000 142.840 0.600 143.440 ;
    END
  END la_data_out[104]
  PIN la_data_out[105]
    DIRECTION OUTPUT ;
    USE SIGNAL ;
    PORT
      LAYER met3 ;
        RECT 0.000 144.200 0.600 144.800 ;
    END
  END la_data_out[105]
  PIN la_data_out[106]
    DIRECTION OUTPUT ;
    USE SIGNAL ;
    PORT
      LAYER met3 ;
        RECT 0.000 145.560 0.600 146.160 ;
    END
  END la_data_out[106]
  PIN la_data_out[107]
    DIRECTION OUTPUT ;
    USE SIGNAL ;
    PORT
      LAYER met3 ;
        RECT 0.000 146.920 0.600 147.520 ;
    END
  END la_data_out[107]
  PIN la_data_out[108]
    DIRECTION OUTPUT ;
    USE SIGNAL ;
    PORT
      LAYER met3 ;
        RECT 0.000 148.280 0.600 148.880 ;
    END
  END la_data_out[108]
  PIN la_data_out[109]
    DIRECTION OUTPUT ;
    USE SIGNAL ;
    PORT
      LAYER met3 ;
        RECT 0.000 149.640 0.600 150.240 ;
    END
  END la_data_out[109]
  PIN la_data_out[10]
    DIRECTION OUTPUT ;
    USE SIGNAL ;
    ANTENNADIFFAREA 2.673000 ;
    PORT
      LAYER met3 ;
        RECT 0.000 15.000 0.600 15.600 ;
    END
  END la_data_out[10]
  PIN la_data_out[110]
    DIRECTION OUTPUT ;
    USE SIGNAL ;
    PORT
      LAYER met3 ;
        RECT 0.000 151.000 0.600 151.600 ;
    END
  END la_data_out[110]
  PIN la_data_out[111]
    DIRECTION OUTPUT ;
    USE SIGNAL ;
    PORT
      LAYER met3 ;
        RECT 0.000 152.360 0.600 152.960 ;
    END
  END la_data_out[111]
  PIN la_data_out[112]
    DIRECTION OUTPUT ;
    USE SIGNAL ;
    PORT
      LAYER met3 ;
        RECT 0.000 153.720 0.600 154.320 ;
    END
  END la_data_out[112]
  PIN la_data_out[113]
    DIRECTION OUTPUT ;
    USE SIGNAL ;
    PORT
      LAYER met3 ;
        RECT 0.000 155.080 0.600 155.680 ;
    END
  END la_data_out[113]
  PIN la_data_out[114]
    DIRECTION OUTPUT ;
    USE SIGNAL ;
    PORT
      LAYER met3 ;
        RECT 0.000 156.440 0.600 157.040 ;
    END
  END la_data_out[114]
  PIN la_data_out[115]
    DIRECTION OUTPUT ;
    USE SIGNAL ;
    PORT
      LAYER met3 ;
        RECT 0.000 157.800 0.600 158.400 ;
    END
  END la_data_out[115]
  PIN la_data_out[116]
    DIRECTION OUTPUT ;
    USE SIGNAL ;
    PORT
      LAYER met3 ;
        RECT 0.000 159.160 0.600 159.760 ;
    END
  END la_data_out[116]
  PIN la_data_out[117]
    DIRECTION OUTPUT ;
    USE SIGNAL ;
    PORT
      LAYER met3 ;
        RECT 0.000 160.520 0.600 161.120 ;
    END
  END la_data_out[117]
  PIN la_data_out[118]
    DIRECTION OUTPUT ;
    USE SIGNAL ;
    PORT
      LAYER met3 ;
        RECT 0.000 161.880 0.600 162.480 ;
    END
  END la_data_out[118]
  PIN la_data_out[119]
    DIRECTION OUTPUT ;
    USE SIGNAL ;
    PORT
      LAYER met3 ;
        RECT 0.000 163.240 0.600 163.840 ;
    END
  END la_data_out[119]
  PIN la_data_out[11]
    DIRECTION OUTPUT ;
    USE SIGNAL ;
    ANTENNADIFFAREA 2.673000 ;
    PORT
      LAYER met3 ;
        RECT 0.000 16.360 0.600 16.960 ;
    END
  END la_data_out[11]
  PIN la_data_out[120]
    DIRECTION OUTPUT ;
    USE SIGNAL ;
    PORT
      LAYER met3 ;
        RECT 0.000 164.600 0.600 165.200 ;
    END
  END la_data_out[120]
  PIN la_data_out[121]
    DIRECTION OUTPUT ;
    USE SIGNAL ;
    PORT
      LAYER met3 ;
        RECT 0.000 165.960 0.600 166.560 ;
    END
  END la_data_out[121]
  PIN la_data_out[122]
    DIRECTION OUTPUT ;
    USE SIGNAL ;
    PORT
      LAYER met3 ;
        RECT 0.000 167.320 0.600 167.920 ;
    END
  END la_data_out[122]
  PIN la_data_out[123]
    DIRECTION OUTPUT ;
    USE SIGNAL ;
    PORT
      LAYER met3 ;
        RECT 0.000 168.680 0.600 169.280 ;
    END
  END la_data_out[123]
  PIN la_data_out[124]
    DIRECTION OUTPUT ;
    USE SIGNAL ;
    PORT
      LAYER met3 ;
        RECT 0.000 170.040 0.600 170.640 ;
    END
  END la_data_out[124]
  PIN la_data_out[125]
    DIRECTION OUTPUT ;
    USE SIGNAL ;
    PORT
      LAYER met3 ;
        RECT 0.000 171.400 0.600 172.000 ;
    END
  END la_data_out[125]
  PIN la_data_out[126]
    DIRECTION OUTPUT ;
    USE SIGNAL ;
    PORT
      LAYER met3 ;
        RECT 0.000 172.760 0.600 173.360 ;
    END
  END la_data_out[126]
  PIN la_data_out[127]
    DIRECTION OUTPUT ;
    USE SIGNAL ;
    PORT
      LAYER met3 ;
        RECT 0.000 174.120 0.600 174.720 ;
    END
  END la_data_out[127]
  PIN la_data_out[12]
    DIRECTION OUTPUT ;
    USE SIGNAL ;
    ANTENNADIFFAREA 2.673000 ;
    PORT
      LAYER met3 ;
        RECT 0.000 17.720 0.600 18.320 ;
    END
  END la_data_out[12]
  PIN la_data_out[13]
    DIRECTION OUTPUT ;
    USE SIGNAL ;
    ANTENNADIFFAREA 2.673000 ;
    PORT
      LAYER met3 ;
        RECT 0.000 19.080 0.600 19.680 ;
    END
  END la_data_out[13]
  PIN la_data_out[14]
    DIRECTION OUTPUT ;
    USE SIGNAL ;
    ANTENNADIFFAREA 2.673000 ;
    PORT
      LAYER met3 ;
        RECT 0.000 20.440 0.600 21.040 ;
    END
  END la_data_out[14]
  PIN la_data_out[15]
    DIRECTION OUTPUT ;
    USE SIGNAL ;
    ANTENNADIFFAREA 2.673000 ;
    PORT
      LAYER met3 ;
        RECT 0.000 21.800 0.600 22.400 ;
    END
  END la_data_out[15]
  PIN la_data_out[16]
    DIRECTION OUTPUT ;
    USE SIGNAL ;
    PORT
      LAYER met3 ;
        RECT 0.000 23.160 0.600 23.760 ;
    END
  END la_data_out[16]
  PIN la_data_out[17]
    DIRECTION OUTPUT ;
    USE SIGNAL ;
    PORT
      LAYER met3 ;
        RECT 0.000 24.520 0.600 25.120 ;
    END
  END la_data_out[17]
  PIN la_data_out[18]
    DIRECTION OUTPUT ;
    USE SIGNAL ;
    PORT
      LAYER met3 ;
        RECT 0.000 25.880 0.600 26.480 ;
    END
  END la_data_out[18]
  PIN la_data_out[19]
    DIRECTION OUTPUT ;
    USE SIGNAL ;
    PORT
      LAYER met3 ;
        RECT 0.000 27.240 0.600 27.840 ;
    END
  END la_data_out[19]
  PIN la_data_out[1]
    DIRECTION OUTPUT ;
    USE SIGNAL ;
    ANTENNADIFFAREA 2.673000 ;
    PORT
      LAYER met3 ;
        RECT 0.000 2.760 0.600 3.360 ;
    END
  END la_data_out[1]
  PIN la_data_out[20]
    DIRECTION OUTPUT ;
    USE SIGNAL ;
    PORT
      LAYER met3 ;
        RECT 0.000 28.600 0.600 29.200 ;
    END
  END la_data_out[20]
  PIN la_data_out[21]
    DIRECTION OUTPUT ;
    USE SIGNAL ;
    PORT
      LAYER met3 ;
        RECT 0.000 29.960 0.600 30.560 ;
    END
  END la_data_out[21]
  PIN la_data_out[22]
    DIRECTION OUTPUT ;
    USE SIGNAL ;
    PORT
      LAYER met3 ;
        RECT 0.000 31.320 0.600 31.920 ;
    END
  END la_data_out[22]
  PIN la_data_out[23]
    DIRECTION OUTPUT ;
    USE SIGNAL ;
    PORT
      LAYER met3 ;
        RECT 0.000 32.680 0.600 33.280 ;
    END
  END la_data_out[23]
  PIN la_data_out[24]
    DIRECTION OUTPUT ;
    USE SIGNAL ;
    PORT
      LAYER met3 ;
        RECT 0.000 34.040 0.600 34.640 ;
    END
  END la_data_out[24]
  PIN la_data_out[25]
    DIRECTION OUTPUT ;
    USE SIGNAL ;
    PORT
      LAYER met3 ;
        RECT 0.000 35.400 0.600 36.000 ;
    END
  END la_data_out[25]
  PIN la_data_out[26]
    DIRECTION OUTPUT ;
    USE SIGNAL ;
    PORT
      LAYER met3 ;
        RECT 0.000 36.760 0.600 37.360 ;
    END
  END la_data_out[26]
  PIN la_data_out[27]
    DIRECTION OUTPUT ;
    USE SIGNAL ;
    PORT
      LAYER met3 ;
        RECT 0.000 38.120 0.600 38.720 ;
    END
  END la_data_out[27]
  PIN la_data_out[28]
    DIRECTION OUTPUT ;
    USE SIGNAL ;
    PORT
      LAYER met3 ;
        RECT 0.000 39.480 0.600 40.080 ;
    END
  END la_data_out[28]
  PIN la_data_out[29]
    DIRECTION OUTPUT ;
    USE SIGNAL ;
    PORT
      LAYER met3 ;
        RECT 0.000 40.840 0.600 41.440 ;
    END
  END la_data_out[29]
  PIN la_data_out[2]
    DIRECTION OUTPUT ;
    USE SIGNAL ;
    ANTENNADIFFAREA 2.673000 ;
    PORT
      LAYER met3 ;
        RECT 0.000 4.120 0.600 4.720 ;
    END
  END la_data_out[2]
  PIN la_data_out[30]
    DIRECTION OUTPUT ;
    USE SIGNAL ;
    PORT
      LAYER met3 ;
        RECT 0.000 42.200 0.600 42.800 ;
    END
  END la_data_out[30]
  PIN la_data_out[31]
    DIRECTION OUTPUT ;
    USE SIGNAL ;
    PORT
      LAYER met3 ;
        RECT 0.000 43.560 0.600 44.160 ;
    END
  END la_data_out[31]
  PIN la_data_out[32]
    DIRECTION OUTPUT ;
    USE SIGNAL ;
    PORT
      LAYER met3 ;
        RECT 0.000 44.920 0.600 45.520 ;
    END
  END la_data_out[32]
  PIN la_data_out[33]
    DIRECTION OUTPUT ;
    USE SIGNAL ;
    PORT
      LAYER met3 ;
        RECT 0.000 46.280 0.600 46.880 ;
    END
  END la_data_out[33]
  PIN la_data_out[34]
    DIRECTION OUTPUT ;
    USE SIGNAL ;
    PORT
      LAYER met3 ;
        RECT 0.000 47.640 0.600 48.240 ;
    END
  END la_data_out[34]
  PIN la_data_out[35]
    DIRECTION OUTPUT ;
    USE SIGNAL ;
    PORT
      LAYER met3 ;
        RECT 0.000 49.000 0.600 49.600 ;
    END
  END la_data_out[35]
  PIN la_data_out[36]
    DIRECTION OUTPUT ;
    USE SIGNAL ;
    PORT
      LAYER met3 ;
        RECT 0.000 50.360 0.600 50.960 ;
    END
  END la_data_out[36]
  PIN la_data_out[37]
    DIRECTION OUTPUT ;
    USE SIGNAL ;
    PORT
      LAYER met3 ;
        RECT 0.000 51.720 0.600 52.320 ;
    END
  END la_data_out[37]
  PIN la_data_out[38]
    DIRECTION OUTPUT ;
    USE SIGNAL ;
    PORT
      LAYER met3 ;
        RECT 0.000 53.080 0.600 53.680 ;
    END
  END la_data_out[38]
  PIN la_data_out[39]
    DIRECTION OUTPUT ;
    USE SIGNAL ;
    PORT
      LAYER met3 ;
        RECT 0.000 54.440 0.600 55.040 ;
    END
  END la_data_out[39]
  PIN la_data_out[3]
    DIRECTION OUTPUT ;
    USE SIGNAL ;
    ANTENNADIFFAREA 2.673000 ;
    PORT
      LAYER met3 ;
        RECT 0.000 5.480 0.600 6.080 ;
    END
  END la_data_out[3]
  PIN la_data_out[40]
    DIRECTION OUTPUT ;
    USE SIGNAL ;
    PORT
      LAYER met3 ;
        RECT 0.000 55.800 0.600 56.400 ;
    END
  END la_data_out[40]
  PIN la_data_out[41]
    DIRECTION OUTPUT ;
    USE SIGNAL ;
    PORT
      LAYER met3 ;
        RECT 0.000 57.160 0.600 57.760 ;
    END
  END la_data_out[41]
  PIN la_data_out[42]
    DIRECTION OUTPUT ;
    USE SIGNAL ;
    PORT
      LAYER met3 ;
        RECT 0.000 58.520 0.600 59.120 ;
    END
  END la_data_out[42]
  PIN la_data_out[43]
    DIRECTION OUTPUT ;
    USE SIGNAL ;
    PORT
      LAYER met3 ;
        RECT 0.000 59.880 0.600 60.480 ;
    END
  END la_data_out[43]
  PIN la_data_out[44]
    DIRECTION OUTPUT ;
    USE SIGNAL ;
    PORT
      LAYER met3 ;
        RECT 0.000 61.240 0.600 61.840 ;
    END
  END la_data_out[44]
  PIN la_data_out[45]
    DIRECTION OUTPUT ;
    USE SIGNAL ;
    PORT
      LAYER met3 ;
        RECT 0.000 62.600 0.600 63.200 ;
    END
  END la_data_out[45]
  PIN la_data_out[46]
    DIRECTION OUTPUT ;
    USE SIGNAL ;
    PORT
      LAYER met3 ;
        RECT 0.000 63.960 0.600 64.560 ;
    END
  END la_data_out[46]
  PIN la_data_out[47]
    DIRECTION OUTPUT ;
    USE SIGNAL ;
    PORT
      LAYER met3 ;
        RECT 0.000 65.320 0.600 65.920 ;
    END
  END la_data_out[47]
  PIN la_data_out[48]
    DIRECTION OUTPUT ;
    USE SIGNAL ;
    PORT
      LAYER met3 ;
        RECT 0.000 66.680 0.600 67.280 ;
    END
  END la_data_out[48]
  PIN la_data_out[49]
    DIRECTION OUTPUT ;
    USE SIGNAL ;
    PORT
      LAYER met3 ;
        RECT 0.000 68.040 0.600 68.640 ;
    END
  END la_data_out[49]
  PIN la_data_out[4]
    DIRECTION OUTPUT ;
    USE SIGNAL ;
    ANTENNADIFFAREA 2.673000 ;
    PORT
      LAYER met3 ;
        RECT 0.000 6.840 0.600 7.440 ;
    END
  END la_data_out[4]
  PIN la_data_out[50]
    DIRECTION OUTPUT ;
    USE SIGNAL ;
    PORT
      LAYER met3 ;
        RECT 0.000 69.400 0.600 70.000 ;
    END
  END la_data_out[50]
  PIN la_data_out[51]
    DIRECTION OUTPUT ;
    USE SIGNAL ;
    PORT
      LAYER met3 ;
        RECT 0.000 70.760 0.600 71.360 ;
    END
  END la_data_out[51]
  PIN la_data_out[52]
    DIRECTION OUTPUT ;
    USE SIGNAL ;
    PORT
      LAYER met3 ;
        RECT 0.000 72.120 0.600 72.720 ;
    END
  END la_data_out[52]
  PIN la_data_out[53]
    DIRECTION OUTPUT ;
    USE SIGNAL ;
    PORT
      LAYER met3 ;
        RECT 0.000 73.480 0.600 74.080 ;
    END
  END la_data_out[53]
  PIN la_data_out[54]
    DIRECTION OUTPUT ;
    USE SIGNAL ;
    PORT
      LAYER met3 ;
        RECT 0.000 74.840 0.600 75.440 ;
    END
  END la_data_out[54]
  PIN la_data_out[55]
    DIRECTION OUTPUT ;
    USE SIGNAL ;
    PORT
      LAYER met3 ;
        RECT 0.000 76.200 0.600 76.800 ;
    END
  END la_data_out[55]
  PIN la_data_out[56]
    DIRECTION OUTPUT ;
    USE SIGNAL ;
    PORT
      LAYER met3 ;
        RECT 0.000 77.560 0.600 78.160 ;
    END
  END la_data_out[56]
  PIN la_data_out[57]
    DIRECTION OUTPUT ;
    USE SIGNAL ;
    PORT
      LAYER met3 ;
        RECT 0.000 78.920 0.600 79.520 ;
    END
  END la_data_out[57]
  PIN la_data_out[58]
    DIRECTION OUTPUT ;
    USE SIGNAL ;
    PORT
      LAYER met3 ;
        RECT 0.000 80.280 0.600 80.880 ;
    END
  END la_data_out[58]
  PIN la_data_out[59]
    DIRECTION OUTPUT ;
    USE SIGNAL ;
    PORT
      LAYER met3 ;
        RECT 0.000 81.640 0.600 82.240 ;
    END
  END la_data_out[59]
  PIN la_data_out[5]
    DIRECTION OUTPUT ;
    USE SIGNAL ;
    ANTENNADIFFAREA 2.673000 ;
    PORT
      LAYER met3 ;
        RECT 0.000 8.200 0.600 8.800 ;
    END
  END la_data_out[5]
  PIN la_data_out[60]
    DIRECTION OUTPUT ;
    USE SIGNAL ;
    PORT
      LAYER met3 ;
        RECT 0.000 83.000 0.600 83.600 ;
    END
  END la_data_out[60]
  PIN la_data_out[61]
    DIRECTION OUTPUT ;
    USE SIGNAL ;
    PORT
      LAYER met3 ;
        RECT 0.000 84.360 0.600 84.960 ;
    END
  END la_data_out[61]
  PIN la_data_out[62]
    DIRECTION OUTPUT ;
    USE SIGNAL ;
    PORT
      LAYER met3 ;
        RECT 0.000 85.720 0.600 86.320 ;
    END
  END la_data_out[62]
  PIN la_data_out[63]
    DIRECTION OUTPUT ;
    USE SIGNAL ;
    PORT
      LAYER met3 ;
        RECT 0.000 87.080 0.600 87.680 ;
    END
  END la_data_out[63]
  PIN la_data_out[64]
    DIRECTION OUTPUT ;
    USE SIGNAL ;
    PORT
      LAYER met3 ;
        RECT 0.000 88.440 0.600 89.040 ;
    END
  END la_data_out[64]
  PIN la_data_out[65]
    DIRECTION OUTPUT ;
    USE SIGNAL ;
    PORT
      LAYER met3 ;
        RECT 0.000 89.800 0.600 90.400 ;
    END
  END la_data_out[65]
  PIN la_data_out[66]
    DIRECTION OUTPUT ;
    USE SIGNAL ;
    PORT
      LAYER met3 ;
        RECT 0.000 91.160 0.600 91.760 ;
    END
  END la_data_out[66]
  PIN la_data_out[67]
    DIRECTION OUTPUT ;
    USE SIGNAL ;
    PORT
      LAYER met3 ;
        RECT 0.000 92.520 0.600 93.120 ;
    END
  END la_data_out[67]
  PIN la_data_out[68]
    DIRECTION OUTPUT ;
    USE SIGNAL ;
    PORT
      LAYER met3 ;
        RECT 0.000 93.880 0.600 94.480 ;
    END
  END la_data_out[68]
  PIN la_data_out[69]
    DIRECTION OUTPUT ;
    USE SIGNAL ;
    PORT
      LAYER met3 ;
        RECT 0.000 95.240 0.600 95.840 ;
    END
  END la_data_out[69]
  PIN la_data_out[6]
    DIRECTION OUTPUT ;
    USE SIGNAL ;
    ANTENNADIFFAREA 2.673000 ;
    PORT
      LAYER met3 ;
        RECT 0.000 9.560 0.600 10.160 ;
    END
  END la_data_out[6]
  PIN la_data_out[70]
    DIRECTION OUTPUT ;
    USE SIGNAL ;
    PORT
      LAYER met3 ;
        RECT 0.000 96.600 0.600 97.200 ;
    END
  END la_data_out[70]
  PIN la_data_out[71]
    DIRECTION OUTPUT ;
    USE SIGNAL ;
    PORT
      LAYER met3 ;
        RECT 0.000 97.960 0.600 98.560 ;
    END
  END la_data_out[71]
  PIN la_data_out[72]
    DIRECTION OUTPUT ;
    USE SIGNAL ;
    PORT
      LAYER met3 ;
        RECT 0.000 99.320 0.600 99.920 ;
    END
  END la_data_out[72]
  PIN la_data_out[73]
    DIRECTION OUTPUT ;
    USE SIGNAL ;
    PORT
      LAYER met3 ;
        RECT 0.000 100.680 0.600 101.280 ;
    END
  END la_data_out[73]
  PIN la_data_out[74]
    DIRECTION OUTPUT ;
    USE SIGNAL ;
    PORT
      LAYER met3 ;
        RECT 0.000 102.040 0.600 102.640 ;
    END
  END la_data_out[74]
  PIN la_data_out[75]
    DIRECTION OUTPUT ;
    USE SIGNAL ;
    PORT
      LAYER met3 ;
        RECT 0.000 103.400 0.600 104.000 ;
    END
  END la_data_out[75]
  PIN la_data_out[76]
    DIRECTION OUTPUT ;
    USE SIGNAL ;
    PORT
      LAYER met3 ;
        RECT 0.000 104.760 0.600 105.360 ;
    END
  END la_data_out[76]
  PIN la_data_out[77]
    DIRECTION OUTPUT ;
    USE SIGNAL ;
    PORT
      LAYER met3 ;
        RECT 0.000 106.120 0.600 106.720 ;
    END
  END la_data_out[77]
  PIN la_data_out[78]
    DIRECTION OUTPUT ;
    USE SIGNAL ;
    PORT
      LAYER met3 ;
        RECT 0.000 107.480 0.600 108.080 ;
    END
  END la_data_out[78]
  PIN la_data_out[79]
    DIRECTION OUTPUT ;
    USE SIGNAL ;
    PORT
      LAYER met3 ;
        RECT 0.000 108.840 0.600 109.440 ;
    END
  END la_data_out[79]
  PIN la_data_out[7]
    DIRECTION OUTPUT ;
    USE SIGNAL ;
    ANTENNADIFFAREA 2.673000 ;
    PORT
      LAYER met3 ;
        RECT 0.000 10.920 0.600 11.520 ;
    END
  END la_data_out[7]
  PIN la_data_out[80]
    DIRECTION OUTPUT ;
    USE SIGNAL ;
    PORT
      LAYER met3 ;
        RECT 0.000 110.200 0.600 110.800 ;
    END
  END la_data_out[80]
  PIN la_data_out[81]
    DIRECTION OUTPUT ;
    USE SIGNAL ;
    PORT
      LAYER met3 ;
        RECT 0.000 111.560 0.600 112.160 ;
    END
  END la_data_out[81]
  PIN la_data_out[82]
    DIRECTION OUTPUT ;
    USE SIGNAL ;
    PORT
      LAYER met3 ;
        RECT 0.000 112.920 0.600 113.520 ;
    END
  END la_data_out[82]
  PIN la_data_out[83]
    DIRECTION OUTPUT ;
    USE SIGNAL ;
    PORT
      LAYER met3 ;
        RECT 0.000 114.280 0.600 114.880 ;
    END
  END la_data_out[83]
  PIN la_data_out[84]
    DIRECTION OUTPUT ;
    USE SIGNAL ;
    PORT
      LAYER met3 ;
        RECT 0.000 115.640 0.600 116.240 ;
    END
  END la_data_out[84]
  PIN la_data_out[85]
    DIRECTION OUTPUT ;
    USE SIGNAL ;
    PORT
      LAYER met3 ;
        RECT 0.000 117.000 0.600 117.600 ;
    END
  END la_data_out[85]
  PIN la_data_out[86]
    DIRECTION OUTPUT ;
    USE SIGNAL ;
    PORT
      LAYER met3 ;
        RECT 0.000 118.360 0.600 118.960 ;
    END
  END la_data_out[86]
  PIN la_data_out[87]
    DIRECTION OUTPUT ;
    USE SIGNAL ;
    PORT
      LAYER met3 ;
        RECT 0.000 119.720 0.600 120.320 ;
    END
  END la_data_out[87]
  PIN la_data_out[88]
    DIRECTION OUTPUT ;
    USE SIGNAL ;
    PORT
      LAYER met3 ;
        RECT 0.000 121.080 0.600 121.680 ;
    END
  END la_data_out[88]
  PIN la_data_out[89]
    DIRECTION OUTPUT ;
    USE SIGNAL ;
    PORT
      LAYER met3 ;
        RECT 0.000 122.440 0.600 123.040 ;
    END
  END la_data_out[89]
  PIN la_data_out[8]
    DIRECTION OUTPUT ;
    USE SIGNAL ;
    ANTENNADIFFAREA 2.673000 ;
    PORT
      LAYER met3 ;
        RECT 0.000 12.280 0.600 12.880 ;
    END
  END la_data_out[8]
  PIN la_data_out[90]
    DIRECTION OUTPUT ;
    USE SIGNAL ;
    PORT
      LAYER met3 ;
        RECT 0.000 123.800 0.600 124.400 ;
    END
  END la_data_out[90]
  PIN la_data_out[91]
    DIRECTION OUTPUT ;
    USE SIGNAL ;
    PORT
      LAYER met3 ;
        RECT 0.000 125.160 0.600 125.760 ;
    END
  END la_data_out[91]
  PIN la_data_out[92]
    DIRECTION OUTPUT ;
    USE SIGNAL ;
    PORT
      LAYER met3 ;
        RECT 0.000 126.520 0.600 127.120 ;
    END
  END la_data_out[92]
  PIN la_data_out[93]
    DIRECTION OUTPUT ;
    USE SIGNAL ;
    PORT
      LAYER met3 ;
        RECT 0.000 127.880 0.600 128.480 ;
    END
  END la_data_out[93]
  PIN la_data_out[94]
    DIRECTION OUTPUT ;
    USE SIGNAL ;
    PORT
      LAYER met3 ;
        RECT 0.000 129.240 0.600 129.840 ;
    END
  END la_data_out[94]
  PIN la_data_out[95]
    DIRECTION OUTPUT ;
    USE SIGNAL ;
    PORT
      LAYER met3 ;
        RECT 0.000 130.600 0.600 131.200 ;
    END
  END la_data_out[95]
  PIN la_data_out[96]
    DIRECTION OUTPUT ;
    USE SIGNAL ;
    PORT
      LAYER met3 ;
        RECT 0.000 131.960 0.600 132.560 ;
    END
  END la_data_out[96]
  PIN la_data_out[97]
    DIRECTION OUTPUT ;
    USE SIGNAL ;
    PORT
      LAYER met3 ;
        RECT 0.000 133.320 0.600 133.920 ;
    END
  END la_data_out[97]
  PIN la_data_out[98]
    DIRECTION OUTPUT ;
    USE SIGNAL ;
    PORT
      LAYER met3 ;
        RECT 0.000 134.680 0.600 135.280 ;
    END
  END la_data_out[98]
  PIN la_data_out[99]
    DIRECTION OUTPUT ;
    USE SIGNAL ;
    PORT
      LAYER met3 ;
        RECT 0.000 136.040 0.600 136.640 ;
    END
  END la_data_out[99]
  PIN la_data_out[9]
    DIRECTION OUTPUT ;
    USE SIGNAL ;
    ANTENNADIFFAREA 2.673000 ;
    PORT
      LAYER met3 ;
        RECT 0.000 13.640 0.600 14.240 ;
    END
  END la_data_out[9]
  PIN la_oenb[0]
    DIRECTION INPUT ;
    USE SIGNAL ;
    PORT
      LAYER met3 ;
        RECT 199.400 1.400 200.000 2.000 ;
    END
  END la_oenb[0]
  PIN la_oenb[100]
    DIRECTION INPUT ;
    USE SIGNAL ;
    PORT
      LAYER met3 ;
        RECT 199.400 137.400 200.000 138.000 ;
    END
  END la_oenb[100]
  PIN la_oenb[101]
    DIRECTION INPUT ;
    USE SIGNAL ;
    PORT
      LAYER met3 ;
        RECT 199.400 138.760 200.000 139.360 ;
    END
  END la_oenb[101]
  PIN la_oenb[102]
    DIRECTION INPUT ;
    USE SIGNAL ;
    PORT
      LAYER met3 ;
        RECT 199.400 140.120 200.000 140.720 ;
    END
  END la_oenb[102]
  PIN la_oenb[103]
    DIRECTION INPUT ;
    USE SIGNAL ;
    PORT
      LAYER met3 ;
        RECT 199.400 141.480 200.000 142.080 ;
    END
  END la_oenb[103]
  PIN la_oenb[104]
    DIRECTION INPUT ;
    USE SIGNAL ;
    PORT
      LAYER met3 ;
        RECT 199.400 142.840 200.000 143.440 ;
    END
  END la_oenb[104]
  PIN la_oenb[105]
    DIRECTION INPUT ;
    USE SIGNAL ;
    PORT
      LAYER met3 ;
        RECT 199.400 144.200 200.000 144.800 ;
    END
  END la_oenb[105]
  PIN la_oenb[106]
    DIRECTION INPUT ;
    USE SIGNAL ;
    PORT
      LAYER met3 ;
        RECT 199.400 145.560 200.000 146.160 ;
    END
  END la_oenb[106]
  PIN la_oenb[107]
    DIRECTION INPUT ;
    USE SIGNAL ;
    PORT
      LAYER met3 ;
        RECT 199.400 146.920 200.000 147.520 ;
    END
  END la_oenb[107]
  PIN la_oenb[108]
    DIRECTION INPUT ;
    USE SIGNAL ;
    PORT
      LAYER met3 ;
        RECT 199.400 148.280 200.000 148.880 ;
    END
  END la_oenb[108]
  PIN la_oenb[109]
    DIRECTION INPUT ;
    USE SIGNAL ;
    PORT
      LAYER met3 ;
        RECT 199.400 149.640 200.000 150.240 ;
    END
  END la_oenb[109]
  PIN la_oenb[10]
    DIRECTION INPUT ;
    USE SIGNAL ;
    PORT
      LAYER met3 ;
        RECT 199.400 15.000 200.000 15.600 ;
    END
  END la_oenb[10]
  PIN la_oenb[110]
    DIRECTION INPUT ;
    USE SIGNAL ;
    PORT
      LAYER met3 ;
        RECT 199.400 151.000 200.000 151.600 ;
    END
  END la_oenb[110]
  PIN la_oenb[111]
    DIRECTION INPUT ;
    USE SIGNAL ;
    PORT
      LAYER met3 ;
        RECT 199.400 152.360 200.000 152.960 ;
    END
  END la_oenb[111]
  PIN la_oenb[112]
    DIRECTION INPUT ;
    USE SIGNAL ;
    PORT
      LAYER met3 ;
        RECT 199.400 153.720 200.000 154.320 ;
    END
  END la_oenb[112]
  PIN la_oenb[113]
    DIRECTION INPUT ;
    USE SIGNAL ;
    PORT
      LAYER met3 ;
        RECT 199.400 155.080 200.000 155.680 ;
    END
  END la_oenb[113]
  PIN la_oenb[114]
    DIRECTION INPUT ;
    USE SIGNAL ;
    PORT
      LAYER met3 ;
        RECT 199.400 156.440 200.000 157.040 ;
    END
  END la_oenb[114]
  PIN la_oenb[115]
    DIRECTION INPUT ;
    USE SIGNAL ;
    PORT
      LAYER met3 ;
        RECT 199.400 157.800 200.000 158.400 ;
    END
  END la_oenb[115]
  PIN la_oenb[116]
    DIRECTION INPUT ;
    USE SIGNAL ;
    PORT
      LAYER met3 ;
        RECT 199.400 159.160 200.000 159.760 ;
    END
  END la_oenb[116]
  PIN la_oenb[117]
    DIRECTION INPUT ;
    USE SIGNAL ;
    PORT
      LAYER met3 ;
        RECT 199.400 160.520 200.000 161.120 ;
    END
  END la_oenb[117]
  PIN la_oenb[118]
    DIRECTION INPUT ;
    USE SIGNAL ;
    PORT
      LAYER met3 ;
        RECT 199.400 161.880 200.000 162.480 ;
    END
  END la_oenb[118]
  PIN la_oenb[119]
    DIRECTION INPUT ;
    USE SIGNAL ;
    PORT
      LAYER met3 ;
        RECT 199.400 163.240 200.000 163.840 ;
    END
  END la_oenb[119]
  PIN la_oenb[11]
    DIRECTION INPUT ;
    USE SIGNAL ;
    PORT
      LAYER met3 ;
        RECT 199.400 16.360 200.000 16.960 ;
    END
  END la_oenb[11]
  PIN la_oenb[120]
    DIRECTION INPUT ;
    USE SIGNAL ;
    PORT
      LAYER met3 ;
        RECT 199.400 164.600 200.000 165.200 ;
    END
  END la_oenb[120]
  PIN la_oenb[121]
    DIRECTION INPUT ;
    USE SIGNAL ;
    PORT
      LAYER met3 ;
        RECT 199.400 165.960 200.000 166.560 ;
    END
  END la_oenb[121]
  PIN la_oenb[122]
    DIRECTION INPUT ;
    USE SIGNAL ;
    PORT
      LAYER met3 ;
        RECT 199.400 167.320 200.000 167.920 ;
    END
  END la_oenb[122]
  PIN la_oenb[123]
    DIRECTION INPUT ;
    USE SIGNAL ;
    PORT
      LAYER met3 ;
        RECT 199.400 168.680 200.000 169.280 ;
    END
  END la_oenb[123]
  PIN la_oenb[124]
    DIRECTION INPUT ;
    USE SIGNAL ;
    PORT
      LAYER met3 ;
        RECT 199.400 170.040 200.000 170.640 ;
    END
  END la_oenb[124]
  PIN la_oenb[125]
    DIRECTION INPUT ;
    USE SIGNAL ;
    PORT
      LAYER met3 ;
        RECT 199.400 171.400 200.000 172.000 ;
    END
  END la_oenb[125]
  PIN la_oenb[126]
    DIRECTION INPUT ;
    USE SIGNAL ;
    PORT
      LAYER met3 ;
        RECT 199.400 172.760 200.000 173.360 ;
    END
  END la_oenb[126]
  PIN la_oenb[127]
    DIRECTION INPUT ;
    USE SIGNAL ;
    PORT
      LAYER met3 ;
        RECT 199.400 174.120 200.000 174.720 ;
    END
  END la_oenb[127]
  PIN la_oenb[12]
    DIRECTION INPUT ;
    USE SIGNAL ;
    PORT
      LAYER met3 ;
        RECT 199.400 17.720 200.000 18.320 ;
    END
  END la_oenb[12]
  PIN la_oenb[13]
    DIRECTION INPUT ;
    USE SIGNAL ;
    PORT
      LAYER met3 ;
        RECT 199.400 19.080 200.000 19.680 ;
    END
  END la_oenb[13]
  PIN la_oenb[14]
    DIRECTION INPUT ;
    USE SIGNAL ;
    PORT
      LAYER met3 ;
        RECT 199.400 20.440 200.000 21.040 ;
    END
  END la_oenb[14]
  PIN la_oenb[15]
    DIRECTION INPUT ;
    USE SIGNAL ;
    PORT
      LAYER met3 ;
        RECT 199.400 21.800 200.000 22.400 ;
    END
  END la_oenb[15]
  PIN la_oenb[16]
    DIRECTION INPUT ;
    USE SIGNAL ;
    PORT
      LAYER met3 ;
        RECT 199.400 23.160 200.000 23.760 ;
    END
  END la_oenb[16]
  PIN la_oenb[17]
    DIRECTION INPUT ;
    USE SIGNAL ;
    PORT
      LAYER met3 ;
        RECT 199.400 24.520 200.000 25.120 ;
    END
  END la_oenb[17]
  PIN la_oenb[18]
    DIRECTION INPUT ;
    USE SIGNAL ;
    PORT
      LAYER met3 ;
        RECT 199.400 25.880 200.000 26.480 ;
    END
  END la_oenb[18]
  PIN la_oenb[19]
    DIRECTION INPUT ;
    USE SIGNAL ;
    PORT
      LAYER met3 ;
        RECT 199.400 27.240 200.000 27.840 ;
    END
  END la_oenb[19]
  PIN la_oenb[1]
    DIRECTION INPUT ;
    USE SIGNAL ;
    PORT
      LAYER met3 ;
        RECT 199.400 2.760 200.000 3.360 ;
    END
  END la_oenb[1]
  PIN la_oenb[20]
    DIRECTION INPUT ;
    USE SIGNAL ;
    PORT
      LAYER met3 ;
        RECT 199.400 28.600 200.000 29.200 ;
    END
  END la_oenb[20]
  PIN la_oenb[21]
    DIRECTION INPUT ;
    USE SIGNAL ;
    PORT
      LAYER met3 ;
        RECT 199.400 29.960 200.000 30.560 ;
    END
  END la_oenb[21]
  PIN la_oenb[22]
    DIRECTION INPUT ;
    USE SIGNAL ;
    PORT
      LAYER met3 ;
        RECT 199.400 31.320 200.000 31.920 ;
    END
  END la_oenb[22]
  PIN la_oenb[23]
    DIRECTION INPUT ;
    USE SIGNAL ;
    PORT
      LAYER met3 ;
        RECT 199.400 32.680 200.000 33.280 ;
    END
  END la_oenb[23]
  PIN la_oenb[24]
    DIRECTION INPUT ;
    USE SIGNAL ;
    PORT
      LAYER met3 ;
        RECT 199.400 34.040 200.000 34.640 ;
    END
  END la_oenb[24]
  PIN la_oenb[25]
    DIRECTION INPUT ;
    USE SIGNAL ;
    PORT
      LAYER met3 ;
        RECT 199.400 35.400 200.000 36.000 ;
    END
  END la_oenb[25]
  PIN la_oenb[26]
    DIRECTION INPUT ;
    USE SIGNAL ;
    PORT
      LAYER met3 ;
        RECT 199.400 36.760 200.000 37.360 ;
    END
  END la_oenb[26]
  PIN la_oenb[27]
    DIRECTION INPUT ;
    USE SIGNAL ;
    PORT
      LAYER met3 ;
        RECT 199.400 38.120 200.000 38.720 ;
    END
  END la_oenb[27]
  PIN la_oenb[28]
    DIRECTION INPUT ;
    USE SIGNAL ;
    PORT
      LAYER met3 ;
        RECT 199.400 39.480 200.000 40.080 ;
    END
  END la_oenb[28]
  PIN la_oenb[29]
    DIRECTION INPUT ;
    USE SIGNAL ;
    PORT
      LAYER met3 ;
        RECT 199.400 40.840 200.000 41.440 ;
    END
  END la_oenb[29]
  PIN la_oenb[2]
    DIRECTION INPUT ;
    USE SIGNAL ;
    PORT
      LAYER met3 ;
        RECT 199.400 4.120 200.000 4.720 ;
    END
  END la_oenb[2]
  PIN la_oenb[30]
    DIRECTION INPUT ;
    USE SIGNAL ;
    PORT
      LAYER met3 ;
        RECT 199.400 42.200 200.000 42.800 ;
    END
  END la_oenb[30]
  PIN la_oenb[31]
    DIRECTION INPUT ;
    USE SIGNAL ;
    PORT
      LAYER met3 ;
        RECT 199.400 43.560 200.000 44.160 ;
    END
  END la_oenb[31]
  PIN la_oenb[32]
    DIRECTION INPUT ;
    USE SIGNAL ;
    PORT
      LAYER met3 ;
        RECT 199.400 44.920 200.000 45.520 ;
    END
  END la_oenb[32]
  PIN la_oenb[33]
    DIRECTION INPUT ;
    USE SIGNAL ;
    PORT
      LAYER met3 ;
        RECT 199.400 46.280 200.000 46.880 ;
    END
  END la_oenb[33]
  PIN la_oenb[34]
    DIRECTION INPUT ;
    USE SIGNAL ;
    PORT
      LAYER met3 ;
        RECT 199.400 47.640 200.000 48.240 ;
    END
  END la_oenb[34]
  PIN la_oenb[35]
    DIRECTION INPUT ;
    USE SIGNAL ;
    PORT
      LAYER met3 ;
        RECT 199.400 49.000 200.000 49.600 ;
    END
  END la_oenb[35]
  PIN la_oenb[36]
    DIRECTION INPUT ;
    USE SIGNAL ;
    PORT
      LAYER met3 ;
        RECT 199.400 50.360 200.000 50.960 ;
    END
  END la_oenb[36]
  PIN la_oenb[37]
    DIRECTION INPUT ;
    USE SIGNAL ;
    PORT
      LAYER met3 ;
        RECT 199.400 51.720 200.000 52.320 ;
    END
  END la_oenb[37]
  PIN la_oenb[38]
    DIRECTION INPUT ;
    USE SIGNAL ;
    PORT
      LAYER met3 ;
        RECT 199.400 53.080 200.000 53.680 ;
    END
  END la_oenb[38]
  PIN la_oenb[39]
    DIRECTION INPUT ;
    USE SIGNAL ;
    PORT
      LAYER met3 ;
        RECT 199.400 54.440 200.000 55.040 ;
    END
  END la_oenb[39]
  PIN la_oenb[3]
    DIRECTION INPUT ;
    USE SIGNAL ;
    PORT
      LAYER met3 ;
        RECT 199.400 5.480 200.000 6.080 ;
    END
  END la_oenb[3]
  PIN la_oenb[40]
    DIRECTION INPUT ;
    USE SIGNAL ;
    PORT
      LAYER met3 ;
        RECT 199.400 55.800 200.000 56.400 ;
    END
  END la_oenb[40]
  PIN la_oenb[41]
    DIRECTION INPUT ;
    USE SIGNAL ;
    PORT
      LAYER met3 ;
        RECT 199.400 57.160 200.000 57.760 ;
    END
  END la_oenb[41]
  PIN la_oenb[42]
    DIRECTION INPUT ;
    USE SIGNAL ;
    PORT
      LAYER met3 ;
        RECT 199.400 58.520 200.000 59.120 ;
    END
  END la_oenb[42]
  PIN la_oenb[43]
    DIRECTION INPUT ;
    USE SIGNAL ;
    PORT
      LAYER met3 ;
        RECT 199.400 59.880 200.000 60.480 ;
    END
  END la_oenb[43]
  PIN la_oenb[44]
    DIRECTION INPUT ;
    USE SIGNAL ;
    PORT
      LAYER met3 ;
        RECT 199.400 61.240 200.000 61.840 ;
    END
  END la_oenb[44]
  PIN la_oenb[45]
    DIRECTION INPUT ;
    USE SIGNAL ;
    PORT
      LAYER met3 ;
        RECT 199.400 62.600 200.000 63.200 ;
    END
  END la_oenb[45]
  PIN la_oenb[46]
    DIRECTION INPUT ;
    USE SIGNAL ;
    PORT
      LAYER met3 ;
        RECT 199.400 63.960 200.000 64.560 ;
    END
  END la_oenb[46]
  PIN la_oenb[47]
    DIRECTION INPUT ;
    USE SIGNAL ;
    PORT
      LAYER met3 ;
        RECT 199.400 65.320 200.000 65.920 ;
    END
  END la_oenb[47]
  PIN la_oenb[48]
    DIRECTION INPUT ;
    USE SIGNAL ;
    ANTENNAGATEAREA 0.647700 ;
    ANTENNADIFFAREA 0.434700 ;
    PORT
      LAYER met3 ;
        RECT 199.400 66.680 200.000 67.280 ;
    END
  END la_oenb[48]
  PIN la_oenb[49]
    DIRECTION INPUT ;
    USE SIGNAL ;
    ANTENNAGATEAREA 0.647700 ;
    ANTENNADIFFAREA 0.434700 ;
    PORT
      LAYER met3 ;
        RECT 199.400 68.040 200.000 68.640 ;
    END
  END la_oenb[49]
  PIN la_oenb[4]
    DIRECTION INPUT ;
    USE SIGNAL ;
    PORT
      LAYER met3 ;
        RECT 199.400 6.840 200.000 7.440 ;
    END
  END la_oenb[4]
  PIN la_oenb[50]
    DIRECTION INPUT ;
    USE SIGNAL ;
    ANTENNAGATEAREA 0.560700 ;
    ANTENNADIFFAREA 0.434700 ;
    PORT
      LAYER met3 ;
        RECT 199.400 69.400 200.000 70.000 ;
    END
  END la_oenb[50]
  PIN la_oenb[51]
    DIRECTION INPUT ;
    USE SIGNAL ;
    ANTENNAGATEAREA 0.560700 ;
    ANTENNADIFFAREA 0.434700 ;
    PORT
      LAYER met3 ;
        RECT 199.400 70.760 200.000 71.360 ;
    END
  END la_oenb[51]
  PIN la_oenb[52]
    DIRECTION INPUT ;
    USE SIGNAL ;
    ANTENNAGATEAREA 0.560700 ;
    ANTENNADIFFAREA 0.434700 ;
    PORT
      LAYER met3 ;
        RECT 199.400 72.120 200.000 72.720 ;
    END
  END la_oenb[52]
  PIN la_oenb[53]
    DIRECTION INPUT ;
    USE SIGNAL ;
    ANTENNAGATEAREA 0.560700 ;
    ANTENNADIFFAREA 0.434700 ;
    PORT
      LAYER met3 ;
        RECT 199.400 73.480 200.000 74.080 ;
    END
  END la_oenb[53]
  PIN la_oenb[54]
    DIRECTION INPUT ;
    USE SIGNAL ;
    ANTENNAGATEAREA 0.560700 ;
    ANTENNADIFFAREA 0.434700 ;
    PORT
      LAYER met3 ;
        RECT 199.400 74.840 200.000 75.440 ;
    END
  END la_oenb[54]
  PIN la_oenb[55]
    DIRECTION INPUT ;
    USE SIGNAL ;
    ANTENNAGATEAREA 0.560700 ;
    ANTENNADIFFAREA 0.434700 ;
    PORT
      LAYER met3 ;
        RECT 199.400 76.200 200.000 76.800 ;
    END
  END la_oenb[55]
  PIN la_oenb[56]
    DIRECTION INPUT ;
    USE SIGNAL ;
    ANTENNAGATEAREA 0.647700 ;
    ANTENNADIFFAREA 0.434700 ;
    PORT
      LAYER met3 ;
        RECT 199.400 77.560 200.000 78.160 ;
    END
  END la_oenb[56]
  PIN la_oenb[57]
    DIRECTION INPUT ;
    USE SIGNAL ;
    ANTENNAGATEAREA 0.560700 ;
    ANTENNADIFFAREA 0.434700 ;
    PORT
      LAYER met3 ;
        RECT 199.400 78.920 200.000 79.520 ;
    END
  END la_oenb[57]
  PIN la_oenb[58]
    DIRECTION INPUT ;
    USE SIGNAL ;
    ANTENNAGATEAREA 0.560700 ;
    ANTENNADIFFAREA 0.434700 ;
    PORT
      LAYER met3 ;
        RECT 199.400 80.280 200.000 80.880 ;
    END
  END la_oenb[58]
  PIN la_oenb[59]
    DIRECTION INPUT ;
    USE SIGNAL ;
    ANTENNAGATEAREA 0.560700 ;
    ANTENNADIFFAREA 0.434700 ;
    PORT
      LAYER met3 ;
        RECT 199.400 81.640 200.000 82.240 ;
    END
  END la_oenb[59]
  PIN la_oenb[5]
    DIRECTION INPUT ;
    USE SIGNAL ;
    PORT
      LAYER met3 ;
        RECT 199.400 8.200 200.000 8.800 ;
    END
  END la_oenb[5]
  PIN la_oenb[60]
    DIRECTION INPUT ;
    USE SIGNAL ;
    ANTENNAGATEAREA 0.560700 ;
    ANTENNADIFFAREA 0.434700 ;
    PORT
      LAYER met3 ;
        RECT 199.400 83.000 200.000 83.600 ;
    END
  END la_oenb[60]
  PIN la_oenb[61]
    DIRECTION INPUT ;
    USE SIGNAL ;
    ANTENNAGATEAREA 0.560700 ;
    ANTENNADIFFAREA 0.434700 ;
    PORT
      LAYER met3 ;
        RECT 199.400 84.360 200.000 84.960 ;
    END
  END la_oenb[61]
  PIN la_oenb[62]
    DIRECTION INPUT ;
    USE SIGNAL ;
    ANTENNAGATEAREA 0.560700 ;
    ANTENNADIFFAREA 0.434700 ;
    PORT
      LAYER met3 ;
        RECT 199.400 85.720 200.000 86.320 ;
    END
  END la_oenb[62]
  PIN la_oenb[63]
    DIRECTION INPUT ;
    USE SIGNAL ;
    ANTENNAGATEAREA 0.647700 ;
    ANTENNADIFFAREA 0.434700 ;
    PORT
      LAYER met3 ;
        RECT 199.400 87.080 200.000 87.680 ;
    END
  END la_oenb[63]
  PIN la_oenb[64]
    DIRECTION INPUT ;
    USE SIGNAL ;
    ANTENNAGATEAREA 0.647700 ;
    ANTENNADIFFAREA 0.434700 ;
    PORT
      LAYER met3 ;
        RECT 199.400 88.440 200.000 89.040 ;
    END
  END la_oenb[64]
  PIN la_oenb[65]
    DIRECTION INPUT ;
    USE SIGNAL ;
    ANTENNAGATEAREA 0.560700 ;
    ANTENNADIFFAREA 0.434700 ;
    PORT
      LAYER met3 ;
        RECT 199.400 89.800 200.000 90.400 ;
    END
  END la_oenb[65]
  PIN la_oenb[66]
    DIRECTION INPUT ;
    USE SIGNAL ;
    PORT
      LAYER met3 ;
        RECT 199.400 91.160 200.000 91.760 ;
    END
  END la_oenb[66]
  PIN la_oenb[67]
    DIRECTION INPUT ;
    USE SIGNAL ;
    PORT
      LAYER met3 ;
        RECT 199.400 92.520 200.000 93.120 ;
    END
  END la_oenb[67]
  PIN la_oenb[68]
    DIRECTION INPUT ;
    USE SIGNAL ;
    PORT
      LAYER met3 ;
        RECT 199.400 93.880 200.000 94.480 ;
    END
  END la_oenb[68]
  PIN la_oenb[69]
    DIRECTION INPUT ;
    USE SIGNAL ;
    PORT
      LAYER met3 ;
        RECT 199.400 95.240 200.000 95.840 ;
    END
  END la_oenb[69]
  PIN la_oenb[6]
    DIRECTION INPUT ;
    USE SIGNAL ;
    PORT
      LAYER met3 ;
        RECT 199.400 9.560 200.000 10.160 ;
    END
  END la_oenb[6]
  PIN la_oenb[70]
    DIRECTION INPUT ;
    USE SIGNAL ;
    PORT
      LAYER met3 ;
        RECT 199.400 96.600 200.000 97.200 ;
    END
  END la_oenb[70]
  PIN la_oenb[71]
    DIRECTION INPUT ;
    USE SIGNAL ;
    PORT
      LAYER met3 ;
        RECT 199.400 97.960 200.000 98.560 ;
    END
  END la_oenb[71]
  PIN la_oenb[72]
    DIRECTION INPUT ;
    USE SIGNAL ;
    PORT
      LAYER met3 ;
        RECT 199.400 99.320 200.000 99.920 ;
    END
  END la_oenb[72]
  PIN la_oenb[73]
    DIRECTION INPUT ;
    USE SIGNAL ;
    PORT
      LAYER met3 ;
        RECT 199.400 100.680 200.000 101.280 ;
    END
  END la_oenb[73]
  PIN la_oenb[74]
    DIRECTION INPUT ;
    USE SIGNAL ;
    PORT
      LAYER met3 ;
        RECT 199.400 102.040 200.000 102.640 ;
    END
  END la_oenb[74]
  PIN la_oenb[75]
    DIRECTION INPUT ;
    USE SIGNAL ;
    PORT
      LAYER met3 ;
        RECT 199.400 103.400 200.000 104.000 ;
    END
  END la_oenb[75]
  PIN la_oenb[76]
    DIRECTION INPUT ;
    USE SIGNAL ;
    PORT
      LAYER met3 ;
        RECT 199.400 104.760 200.000 105.360 ;
    END
  END la_oenb[76]
  PIN la_oenb[77]
    DIRECTION INPUT ;
    USE SIGNAL ;
    PORT
      LAYER met3 ;
        RECT 199.400 106.120 200.000 106.720 ;
    END
  END la_oenb[77]
  PIN la_oenb[78]
    DIRECTION INPUT ;
    USE SIGNAL ;
    PORT
      LAYER met3 ;
        RECT 199.400 107.480 200.000 108.080 ;
    END
  END la_oenb[78]
  PIN la_oenb[79]
    DIRECTION INPUT ;
    USE SIGNAL ;
    PORT
      LAYER met3 ;
        RECT 199.400 108.840 200.000 109.440 ;
    END
  END la_oenb[79]
  PIN la_oenb[7]
    DIRECTION INPUT ;
    USE SIGNAL ;
    PORT
      LAYER met3 ;
        RECT 199.400 10.920 200.000 11.520 ;
    END
  END la_oenb[7]
  PIN la_oenb[80]
    DIRECTION INPUT ;
    USE SIGNAL ;
    PORT
      LAYER met3 ;
        RECT 199.400 110.200 200.000 110.800 ;
    END
  END la_oenb[80]
  PIN la_oenb[81]
    DIRECTION INPUT ;
    USE SIGNAL ;
    PORT
      LAYER met3 ;
        RECT 199.400 111.560 200.000 112.160 ;
    END
  END la_oenb[81]
  PIN la_oenb[82]
    DIRECTION INPUT ;
    USE SIGNAL ;
    PORT
      LAYER met3 ;
        RECT 199.400 112.920 200.000 113.520 ;
    END
  END la_oenb[82]
  PIN la_oenb[83]
    DIRECTION INPUT ;
    USE SIGNAL ;
    PORT
      LAYER met3 ;
        RECT 199.400 114.280 200.000 114.880 ;
    END
  END la_oenb[83]
  PIN la_oenb[84]
    DIRECTION INPUT ;
    USE SIGNAL ;
    PORT
      LAYER met3 ;
        RECT 199.400 115.640 200.000 116.240 ;
    END
  END la_oenb[84]
  PIN la_oenb[85]
    DIRECTION INPUT ;
    USE SIGNAL ;
    PORT
      LAYER met3 ;
        RECT 199.400 117.000 200.000 117.600 ;
    END
  END la_oenb[85]
  PIN la_oenb[86]
    DIRECTION INPUT ;
    USE SIGNAL ;
    PORT
      LAYER met3 ;
        RECT 199.400 118.360 200.000 118.960 ;
    END
  END la_oenb[86]
  PIN la_oenb[87]
    DIRECTION INPUT ;
    USE SIGNAL ;
    PORT
      LAYER met3 ;
        RECT 199.400 119.720 200.000 120.320 ;
    END
  END la_oenb[87]
  PIN la_oenb[88]
    DIRECTION INPUT ;
    USE SIGNAL ;
    PORT
      LAYER met3 ;
        RECT 199.400 121.080 200.000 121.680 ;
    END
  END la_oenb[88]
  PIN la_oenb[89]
    DIRECTION INPUT ;
    USE SIGNAL ;
    PORT
      LAYER met3 ;
        RECT 199.400 122.440 200.000 123.040 ;
    END
  END la_oenb[89]
  PIN la_oenb[8]
    DIRECTION INPUT ;
    USE SIGNAL ;
    PORT
      LAYER met3 ;
        RECT 199.400 12.280 200.000 12.880 ;
    END
  END la_oenb[8]
  PIN la_oenb[90]
    DIRECTION INPUT ;
    USE SIGNAL ;
    PORT
      LAYER met3 ;
        RECT 199.400 123.800 200.000 124.400 ;
    END
  END la_oenb[90]
  PIN la_oenb[91]
    DIRECTION INPUT ;
    USE SIGNAL ;
    PORT
      LAYER met3 ;
        RECT 199.400 125.160 200.000 125.760 ;
    END
  END la_oenb[91]
  PIN la_oenb[92]
    DIRECTION INPUT ;
    USE SIGNAL ;
    PORT
      LAYER met3 ;
        RECT 199.400 126.520 200.000 127.120 ;
    END
  END la_oenb[92]
  PIN la_oenb[93]
    DIRECTION INPUT ;
    USE SIGNAL ;
    PORT
      LAYER met3 ;
        RECT 199.400 127.880 200.000 128.480 ;
    END
  END la_oenb[93]
  PIN la_oenb[94]
    DIRECTION INPUT ;
    USE SIGNAL ;
    PORT
      LAYER met3 ;
        RECT 199.400 129.240 200.000 129.840 ;
    END
  END la_oenb[94]
  PIN la_oenb[95]
    DIRECTION INPUT ;
    USE SIGNAL ;
    PORT
      LAYER met3 ;
        RECT 199.400 130.600 200.000 131.200 ;
    END
  END la_oenb[95]
  PIN la_oenb[96]
    DIRECTION INPUT ;
    USE SIGNAL ;
    PORT
      LAYER met3 ;
        RECT 199.400 131.960 200.000 132.560 ;
    END
  END la_oenb[96]
  PIN la_oenb[97]
    DIRECTION INPUT ;
    USE SIGNAL ;
    PORT
      LAYER met3 ;
        RECT 199.400 133.320 200.000 133.920 ;
    END
  END la_oenb[97]
  PIN la_oenb[98]
    DIRECTION INPUT ;
    USE SIGNAL ;
    PORT
      LAYER met3 ;
        RECT 199.400 134.680 200.000 135.280 ;
    END
  END la_oenb[98]
  PIN la_oenb[99]
    DIRECTION INPUT ;
    USE SIGNAL ;
    PORT
      LAYER met3 ;
        RECT 199.400 136.040 200.000 136.640 ;
    END
  END la_oenb[99]
  PIN la_oenb[9]
    DIRECTION INPUT ;
    USE SIGNAL ;
    PORT
      LAYER met3 ;
        RECT 199.400 13.640 200.000 14.240 ;
    END
  END la_oenb[9]
  PIN vccd1
    DIRECTION INOUT ;
    USE POWER ;
    PORT
      LAYER met4 ;
        RECT 21.040 10.640 22.640 187.920 ;
    END
    PORT
      LAYER met4 ;
        RECT 174.640 10.640 176.240 187.920 ;
    END
  END vccd1
  PIN vssd1
    DIRECTION INOUT ;
    USE GROUND ;
    PORT
      LAYER met4 ;
        RECT 24.340 10.640 25.940 187.920 ;
    END
    PORT
      LAYER met4 ;
        RECT 177.940 10.640 179.540 187.920 ;
    END
  END vssd1
  PIN wb_clk_i
    DIRECTION INPUT ;
    USE SIGNAL ;
    ANTENNAGATEAREA 0.560700 ;
    ANTENNADIFFAREA 0.434700 ;
    PORT
      LAYER met2 ;
        RECT 14.350 199.720 14.630 200.000 ;
    END
  END wb_clk_i
  PIN wb_rst_i
    DIRECTION INPUT ;
    USE SIGNAL ;
    ANTENNAGATEAREA 0.647700 ;
    ANTENNADIFFAREA 0.434700 ;
    PORT
      LAYER met2 ;
        RECT 15.730 199.720 16.010 200.000 ;
    END
  END wb_rst_i
  PIN wbs_ack_o
    DIRECTION OUTPUT ;
    USE SIGNAL ;
    ANTENNADIFFAREA 2.673000 ;
    PORT
      LAYER met2 ;
        RECT 17.110 199.720 17.390 200.000 ;
    END
  END wbs_ack_o
  PIN wbs_adr_i[0]
    DIRECTION INPUT ;
    USE SIGNAL ;
    PORT
      LAYER met2 ;
        RECT 22.630 199.720 22.910 200.000 ;
    END
  END wbs_adr_i[0]
  PIN wbs_adr_i[10]
    DIRECTION INPUT ;
    USE SIGNAL ;
    PORT
      LAYER met2 ;
        RECT 69.550 199.720 69.830 200.000 ;
    END
  END wbs_adr_i[10]
  PIN wbs_adr_i[11]
    DIRECTION INPUT ;
    USE SIGNAL ;
    PORT
      LAYER met2 ;
        RECT 73.690 199.720 73.970 200.000 ;
    END
  END wbs_adr_i[11]
  PIN wbs_adr_i[12]
    DIRECTION INPUT ;
    USE SIGNAL ;
    PORT
      LAYER met2 ;
        RECT 77.830 199.720 78.110 200.000 ;
    END
  END wbs_adr_i[12]
  PIN wbs_adr_i[13]
    DIRECTION INPUT ;
    USE SIGNAL ;
    PORT
      LAYER met2 ;
        RECT 81.970 199.720 82.250 200.000 ;
    END
  END wbs_adr_i[13]
  PIN wbs_adr_i[14]
    DIRECTION INPUT ;
    USE SIGNAL ;
    PORT
      LAYER met2 ;
        RECT 86.110 199.720 86.390 200.000 ;
    END
  END wbs_adr_i[14]
  PIN wbs_adr_i[15]
    DIRECTION INPUT ;
    USE SIGNAL ;
    PORT
      LAYER met2 ;
        RECT 90.250 199.720 90.530 200.000 ;
    END
  END wbs_adr_i[15]
  PIN wbs_adr_i[16]
    DIRECTION INPUT ;
    USE SIGNAL ;
    PORT
      LAYER met2 ;
        RECT 94.390 199.720 94.670 200.000 ;
    END
  END wbs_adr_i[16]
  PIN wbs_adr_i[17]
    DIRECTION INPUT ;
    USE SIGNAL ;
    PORT
      LAYER met2 ;
        RECT 98.530 199.720 98.810 200.000 ;
    END
  END wbs_adr_i[17]
  PIN wbs_adr_i[18]
    DIRECTION INPUT ;
    USE SIGNAL ;
    PORT
      LAYER met2 ;
        RECT 102.670 199.720 102.950 200.000 ;
    END
  END wbs_adr_i[18]
  PIN wbs_adr_i[19]
    DIRECTION INPUT ;
    USE SIGNAL ;
    PORT
      LAYER met2 ;
        RECT 106.810 199.720 107.090 200.000 ;
    END
  END wbs_adr_i[19]
  PIN wbs_adr_i[1]
    DIRECTION INPUT ;
    USE SIGNAL ;
    PORT
      LAYER met2 ;
        RECT 28.150 199.720 28.430 200.000 ;
    END
  END wbs_adr_i[1]
  PIN wbs_adr_i[20]
    DIRECTION INPUT ;
    USE SIGNAL ;
    PORT
      LAYER met2 ;
        RECT 110.950 199.720 111.230 200.000 ;
    END
  END wbs_adr_i[20]
  PIN wbs_adr_i[21]
    DIRECTION INPUT ;
    USE SIGNAL ;
    PORT
      LAYER met2 ;
        RECT 115.090 199.720 115.370 200.000 ;
    END
  END wbs_adr_i[21]
  PIN wbs_adr_i[22]
    DIRECTION INPUT ;
    USE SIGNAL ;
    PORT
      LAYER met2 ;
        RECT 119.230 199.720 119.510 200.000 ;
    END
  END wbs_adr_i[22]
  PIN wbs_adr_i[23]
    DIRECTION INPUT ;
    USE SIGNAL ;
    PORT
      LAYER met2 ;
        RECT 123.370 199.720 123.650 200.000 ;
    END
  END wbs_adr_i[23]
  PIN wbs_adr_i[24]
    DIRECTION INPUT ;
    USE SIGNAL ;
    PORT
      LAYER met2 ;
        RECT 127.510 199.720 127.790 200.000 ;
    END
  END wbs_adr_i[24]
  PIN wbs_adr_i[25]
    DIRECTION INPUT ;
    USE SIGNAL ;
    PORT
      LAYER met2 ;
        RECT 131.650 199.720 131.930 200.000 ;
    END
  END wbs_adr_i[25]
  PIN wbs_adr_i[26]
    DIRECTION INPUT ;
    USE SIGNAL ;
    PORT
      LAYER met2 ;
        RECT 135.790 199.720 136.070 200.000 ;
    END
  END wbs_adr_i[26]
  PIN wbs_adr_i[27]
    DIRECTION INPUT ;
    USE SIGNAL ;
    PORT
      LAYER met2 ;
        RECT 139.930 199.720 140.210 200.000 ;
    END
  END wbs_adr_i[27]
  PIN wbs_adr_i[28]
    DIRECTION INPUT ;
    USE SIGNAL ;
    PORT
      LAYER met2 ;
        RECT 144.070 199.720 144.350 200.000 ;
    END
  END wbs_adr_i[28]
  PIN wbs_adr_i[29]
    DIRECTION INPUT ;
    USE SIGNAL ;
    PORT
      LAYER met2 ;
        RECT 148.210 199.720 148.490 200.000 ;
    END
  END wbs_adr_i[29]
  PIN wbs_adr_i[2]
    DIRECTION INPUT ;
    USE SIGNAL ;
    PORT
      LAYER met2 ;
        RECT 33.670 199.720 33.950 200.000 ;
    END
  END wbs_adr_i[2]
  PIN wbs_adr_i[30]
    DIRECTION INPUT ;
    USE SIGNAL ;
    PORT
      LAYER met2 ;
        RECT 152.350 199.720 152.630 200.000 ;
    END
  END wbs_adr_i[30]
  PIN wbs_adr_i[31]
    DIRECTION INPUT ;
    USE SIGNAL ;
    PORT
      LAYER met2 ;
        RECT 156.490 199.720 156.770 200.000 ;
    END
  END wbs_adr_i[31]
  PIN wbs_adr_i[3]
    DIRECTION INPUT ;
    USE SIGNAL ;
    PORT
      LAYER met2 ;
        RECT 39.190 199.720 39.470 200.000 ;
    END
  END wbs_adr_i[3]
  PIN wbs_adr_i[4]
    DIRECTION INPUT ;
    USE SIGNAL ;
    PORT
      LAYER met2 ;
        RECT 44.710 199.720 44.990 200.000 ;
    END
  END wbs_adr_i[4]
  PIN wbs_adr_i[5]
    DIRECTION INPUT ;
    USE SIGNAL ;
    PORT
      LAYER met2 ;
        RECT 48.850 199.720 49.130 200.000 ;
    END
  END wbs_adr_i[5]
  PIN wbs_adr_i[6]
    DIRECTION INPUT ;
    USE SIGNAL ;
    PORT
      LAYER met2 ;
        RECT 52.990 199.720 53.270 200.000 ;
    END
  END wbs_adr_i[6]
  PIN wbs_adr_i[7]
    DIRECTION INPUT ;
    USE SIGNAL ;
    PORT
      LAYER met2 ;
        RECT 57.130 199.720 57.410 200.000 ;
    END
  END wbs_adr_i[7]
  PIN wbs_adr_i[8]
    DIRECTION INPUT ;
    USE SIGNAL ;
    PORT
      LAYER met2 ;
        RECT 61.270 199.720 61.550 200.000 ;
    END
  END wbs_adr_i[8]
  PIN wbs_adr_i[9]
    DIRECTION INPUT ;
    USE SIGNAL ;
    PORT
      LAYER met2 ;
        RECT 65.410 199.720 65.690 200.000 ;
    END
  END wbs_adr_i[9]
  PIN wbs_cyc_i
    DIRECTION INPUT ;
    USE SIGNAL ;
    ANTENNAGATEAREA 0.647700 ;
    ANTENNADIFFAREA 0.434700 ;
    PORT
      LAYER met2 ;
        RECT 18.490 199.720 18.770 200.000 ;
    END
  END wbs_cyc_i
  PIN wbs_dat_i[0]
    DIRECTION INPUT ;
    USE SIGNAL ;
    ANTENNAGATEAREA 0.560700 ;
    ANTENNADIFFAREA 0.434700 ;
    PORT
      LAYER met2 ;
        RECT 24.010 199.720 24.290 200.000 ;
    END
  END wbs_dat_i[0]
  PIN wbs_dat_i[10]
    DIRECTION INPUT ;
    USE SIGNAL ;
    ANTENNAGATEAREA 0.647700 ;
    ANTENNADIFFAREA 0.434700 ;
    PORT
      LAYER met2 ;
        RECT 70.930 199.720 71.210 200.000 ;
    END
  END wbs_dat_i[10]
  PIN wbs_dat_i[11]
    DIRECTION INPUT ;
    USE SIGNAL ;
    ANTENNAGATEAREA 0.647700 ;
    ANTENNADIFFAREA 0.434700 ;
    PORT
      LAYER met2 ;
        RECT 75.070 199.720 75.350 200.000 ;
    END
  END wbs_dat_i[11]
  PIN wbs_dat_i[12]
    DIRECTION INPUT ;
    USE SIGNAL ;
    ANTENNAGATEAREA 0.647700 ;
    ANTENNADIFFAREA 0.434700 ;
    PORT
      LAYER met2 ;
        RECT 79.210 199.720 79.490 200.000 ;
    END
  END wbs_dat_i[12]
  PIN wbs_dat_i[13]
    DIRECTION INPUT ;
    USE SIGNAL ;
    ANTENNAGATEAREA 0.647700 ;
    ANTENNADIFFAREA 0.434700 ;
    PORT
      LAYER met2 ;
        RECT 83.350 199.720 83.630 200.000 ;
    END
  END wbs_dat_i[13]
  PIN wbs_dat_i[14]
    DIRECTION INPUT ;
    USE SIGNAL ;
    ANTENNAGATEAREA 0.647700 ;
    ANTENNADIFFAREA 0.434700 ;
    PORT
      LAYER met2 ;
        RECT 87.490 199.720 87.770 200.000 ;
    END
  END wbs_dat_i[14]
  PIN wbs_dat_i[15]
    DIRECTION INPUT ;
    USE SIGNAL ;
    ANTENNAGATEAREA 0.647700 ;
    ANTENNADIFFAREA 0.434700 ;
    PORT
      LAYER met2 ;
        RECT 91.630 199.720 91.910 200.000 ;
    END
  END wbs_dat_i[15]
  PIN wbs_dat_i[16]
    DIRECTION INPUT ;
    USE SIGNAL ;
    PORT
      LAYER met2 ;
        RECT 95.770 199.720 96.050 200.000 ;
    END
  END wbs_dat_i[16]
  PIN wbs_dat_i[17]
    DIRECTION INPUT ;
    USE SIGNAL ;
    PORT
      LAYER met2 ;
        RECT 99.910 199.720 100.190 200.000 ;
    END
  END wbs_dat_i[17]
  PIN wbs_dat_i[18]
    DIRECTION INPUT ;
    USE SIGNAL ;
    PORT
      LAYER met2 ;
        RECT 104.050 199.720 104.330 200.000 ;
    END
  END wbs_dat_i[18]
  PIN wbs_dat_i[19]
    DIRECTION INPUT ;
    USE SIGNAL ;
    PORT
      LAYER met2 ;
        RECT 108.190 199.720 108.470 200.000 ;
    END
  END wbs_dat_i[19]
  PIN wbs_dat_i[1]
    DIRECTION INPUT ;
    USE SIGNAL ;
    ANTENNAGATEAREA 0.647700 ;
    ANTENNADIFFAREA 0.434700 ;
    PORT
      LAYER met2 ;
        RECT 29.530 199.720 29.810 200.000 ;
    END
  END wbs_dat_i[1]
  PIN wbs_dat_i[20]
    DIRECTION INPUT ;
    USE SIGNAL ;
    PORT
      LAYER met2 ;
        RECT 112.330 199.720 112.610 200.000 ;
    END
  END wbs_dat_i[20]
  PIN wbs_dat_i[21]
    DIRECTION INPUT ;
    USE SIGNAL ;
    PORT
      LAYER met2 ;
        RECT 116.470 199.720 116.750 200.000 ;
    END
  END wbs_dat_i[21]
  PIN wbs_dat_i[22]
    DIRECTION INPUT ;
    USE SIGNAL ;
    PORT
      LAYER met2 ;
        RECT 120.610 199.720 120.890 200.000 ;
    END
  END wbs_dat_i[22]
  PIN wbs_dat_i[23]
    DIRECTION INPUT ;
    USE SIGNAL ;
    PORT
      LAYER met2 ;
        RECT 124.750 199.720 125.030 200.000 ;
    END
  END wbs_dat_i[23]
  PIN wbs_dat_i[24]
    DIRECTION INPUT ;
    USE SIGNAL ;
    PORT
      LAYER met2 ;
        RECT 128.890 199.720 129.170 200.000 ;
    END
  END wbs_dat_i[24]
  PIN wbs_dat_i[25]
    DIRECTION INPUT ;
    USE SIGNAL ;
    PORT
      LAYER met2 ;
        RECT 133.030 199.720 133.310 200.000 ;
    END
  END wbs_dat_i[25]
  PIN wbs_dat_i[26]
    DIRECTION INPUT ;
    USE SIGNAL ;
    PORT
      LAYER met2 ;
        RECT 137.170 199.720 137.450 200.000 ;
    END
  END wbs_dat_i[26]
  PIN wbs_dat_i[27]
    DIRECTION INPUT ;
    USE SIGNAL ;
    PORT
      LAYER met2 ;
        RECT 141.310 199.720 141.590 200.000 ;
    END
  END wbs_dat_i[27]
  PIN wbs_dat_i[28]
    DIRECTION INPUT ;
    USE SIGNAL ;
    PORT
      LAYER met2 ;
        RECT 145.450 199.720 145.730 200.000 ;
    END
  END wbs_dat_i[28]
  PIN wbs_dat_i[29]
    DIRECTION INPUT ;
    USE SIGNAL ;
    PORT
      LAYER met2 ;
        RECT 149.590 199.720 149.870 200.000 ;
    END
  END wbs_dat_i[29]
  PIN wbs_dat_i[2]
    DIRECTION INPUT ;
    USE SIGNAL ;
    ANTENNAGATEAREA 0.647700 ;
    ANTENNADIFFAREA 0.434700 ;
    PORT
      LAYER met2 ;
        RECT 35.050 199.720 35.330 200.000 ;
    END
  END wbs_dat_i[2]
  PIN wbs_dat_i[30]
    DIRECTION INPUT ;
    USE SIGNAL ;
    PORT
      LAYER met2 ;
        RECT 153.730 199.720 154.010 200.000 ;
    END
  END wbs_dat_i[30]
  PIN wbs_dat_i[31]
    DIRECTION INPUT ;
    USE SIGNAL ;
    PORT
      LAYER met2 ;
        RECT 157.870 199.720 158.150 200.000 ;
    END
  END wbs_dat_i[31]
  PIN wbs_dat_i[3]
    DIRECTION INPUT ;
    USE SIGNAL ;
    ANTENNAGATEAREA 0.647700 ;
    ANTENNADIFFAREA 0.434700 ;
    PORT
      LAYER met2 ;
        RECT 40.570 199.720 40.850 200.000 ;
    END
  END wbs_dat_i[3]
  PIN wbs_dat_i[4]
    DIRECTION INPUT ;
    USE SIGNAL ;
    ANTENNAGATEAREA 0.647700 ;
    ANTENNADIFFAREA 0.434700 ;
    PORT
      LAYER met2 ;
        RECT 46.090 199.720 46.370 200.000 ;
    END
  END wbs_dat_i[4]
  PIN wbs_dat_i[5]
    DIRECTION INPUT ;
    USE SIGNAL ;
    ANTENNAGATEAREA 0.647700 ;
    ANTENNADIFFAREA 0.434700 ;
    PORT
      LAYER met2 ;
        RECT 50.230 199.720 50.510 200.000 ;
    END
  END wbs_dat_i[5]
  PIN wbs_dat_i[6]
    DIRECTION INPUT ;
    USE SIGNAL ;
    ANTENNAGATEAREA 0.647700 ;
    ANTENNADIFFAREA 0.434700 ;
    PORT
      LAYER met2 ;
        RECT 54.370 199.720 54.650 200.000 ;
    END
  END wbs_dat_i[6]
  PIN wbs_dat_i[7]
    DIRECTION INPUT ;
    USE SIGNAL ;
    ANTENNAGATEAREA 0.647700 ;
    ANTENNADIFFAREA 0.434700 ;
    PORT
      LAYER met2 ;
        RECT 58.510 199.720 58.790 200.000 ;
    END
  END wbs_dat_i[7]
  PIN wbs_dat_i[8]
    DIRECTION INPUT ;
    USE SIGNAL ;
    ANTENNAGATEAREA 0.647700 ;
    ANTENNADIFFAREA 0.434700 ;
    PORT
      LAYER met2 ;
        RECT 62.650 199.720 62.930 200.000 ;
    END
  END wbs_dat_i[8]
  PIN wbs_dat_i[9]
    DIRECTION INPUT ;
    USE SIGNAL ;
    ANTENNAGATEAREA 0.647700 ;
    ANTENNADIFFAREA 0.434700 ;
    PORT
      LAYER met2 ;
        RECT 66.790 199.720 67.070 200.000 ;
    END
  END wbs_dat_i[9]
  PIN wbs_dat_o[0]
    DIRECTION OUTPUT ;
    USE SIGNAL ;
    ANTENNADIFFAREA 2.673000 ;
    PORT
      LAYER met2 ;
        RECT 25.390 199.720 25.670 200.000 ;
    END
  END wbs_dat_o[0]
  PIN wbs_dat_o[10]
    DIRECTION OUTPUT ;
    USE SIGNAL ;
    ANTENNADIFFAREA 2.673000 ;
    PORT
      LAYER met2 ;
        RECT 72.310 199.720 72.590 200.000 ;
    END
  END wbs_dat_o[10]
  PIN wbs_dat_o[11]
    DIRECTION OUTPUT ;
    USE SIGNAL ;
    ANTENNADIFFAREA 2.673000 ;
    PORT
      LAYER met2 ;
        RECT 76.450 199.720 76.730 200.000 ;
    END
  END wbs_dat_o[11]
  PIN wbs_dat_o[12]
    DIRECTION OUTPUT ;
    USE SIGNAL ;
    ANTENNADIFFAREA 2.673000 ;
    PORT
      LAYER met2 ;
        RECT 80.590 199.720 80.870 200.000 ;
    END
  END wbs_dat_o[12]
  PIN wbs_dat_o[13]
    DIRECTION OUTPUT ;
    USE SIGNAL ;
    ANTENNADIFFAREA 2.673000 ;
    PORT
      LAYER met2 ;
        RECT 84.730 199.720 85.010 200.000 ;
    END
  END wbs_dat_o[13]
  PIN wbs_dat_o[14]
    DIRECTION OUTPUT ;
    USE SIGNAL ;
    ANTENNADIFFAREA 2.673000 ;
    PORT
      LAYER met2 ;
        RECT 88.870 199.720 89.150 200.000 ;
    END
  END wbs_dat_o[14]
  PIN wbs_dat_o[15]
    DIRECTION OUTPUT ;
    USE SIGNAL ;
    ANTENNADIFFAREA 2.673000 ;
    PORT
      LAYER met2 ;
        RECT 93.010 199.720 93.290 200.000 ;
    END
  END wbs_dat_o[15]
  PIN wbs_dat_o[16]
    DIRECTION OUTPUT ;
    USE SIGNAL ;
    PORT
      LAYER met2 ;
        RECT 97.150 199.720 97.430 200.000 ;
    END
  END wbs_dat_o[16]
  PIN wbs_dat_o[17]
    DIRECTION OUTPUT ;
    USE SIGNAL ;
    PORT
      LAYER met2 ;
        RECT 101.290 199.720 101.570 200.000 ;
    END
  END wbs_dat_o[17]
  PIN wbs_dat_o[18]
    DIRECTION OUTPUT ;
    USE SIGNAL ;
    PORT
      LAYER met2 ;
        RECT 105.430 199.720 105.710 200.000 ;
    END
  END wbs_dat_o[18]
  PIN wbs_dat_o[19]
    DIRECTION OUTPUT ;
    USE SIGNAL ;
    PORT
      LAYER met2 ;
        RECT 109.570 199.720 109.850 200.000 ;
    END
  END wbs_dat_o[19]
  PIN wbs_dat_o[1]
    DIRECTION OUTPUT ;
    USE SIGNAL ;
    ANTENNADIFFAREA 2.673000 ;
    PORT
      LAYER met2 ;
        RECT 30.910 199.720 31.190 200.000 ;
    END
  END wbs_dat_o[1]
  PIN wbs_dat_o[20]
    DIRECTION OUTPUT ;
    USE SIGNAL ;
    PORT
      LAYER met2 ;
        RECT 113.710 199.720 113.990 200.000 ;
    END
  END wbs_dat_o[20]
  PIN wbs_dat_o[21]
    DIRECTION OUTPUT ;
    USE SIGNAL ;
    PORT
      LAYER met2 ;
        RECT 117.850 199.720 118.130 200.000 ;
    END
  END wbs_dat_o[21]
  PIN wbs_dat_o[22]
    DIRECTION OUTPUT ;
    USE SIGNAL ;
    PORT
      LAYER met2 ;
        RECT 121.990 199.720 122.270 200.000 ;
    END
  END wbs_dat_o[22]
  PIN wbs_dat_o[23]
    DIRECTION OUTPUT ;
    USE SIGNAL ;
    PORT
      LAYER met2 ;
        RECT 126.130 199.720 126.410 200.000 ;
    END
  END wbs_dat_o[23]
  PIN wbs_dat_o[24]
    DIRECTION OUTPUT ;
    USE SIGNAL ;
    PORT
      LAYER met2 ;
        RECT 130.270 199.720 130.550 200.000 ;
    END
  END wbs_dat_o[24]
  PIN wbs_dat_o[25]
    DIRECTION OUTPUT ;
    USE SIGNAL ;
    PORT
      LAYER met2 ;
        RECT 134.410 199.720 134.690 200.000 ;
    END
  END wbs_dat_o[25]
  PIN wbs_dat_o[26]
    DIRECTION OUTPUT ;
    USE SIGNAL ;
    PORT
      LAYER met2 ;
        RECT 138.550 199.720 138.830 200.000 ;
    END
  END wbs_dat_o[26]
  PIN wbs_dat_o[27]
    DIRECTION OUTPUT ;
    USE SIGNAL ;
    PORT
      LAYER met2 ;
        RECT 142.690 199.720 142.970 200.000 ;
    END
  END wbs_dat_o[27]
  PIN wbs_dat_o[28]
    DIRECTION OUTPUT ;
    USE SIGNAL ;
    PORT
      LAYER met2 ;
        RECT 146.830 199.720 147.110 200.000 ;
    END
  END wbs_dat_o[28]
  PIN wbs_dat_o[29]
    DIRECTION OUTPUT ;
    USE SIGNAL ;
    PORT
      LAYER met2 ;
        RECT 150.970 199.720 151.250 200.000 ;
    END
  END wbs_dat_o[29]
  PIN wbs_dat_o[2]
    DIRECTION OUTPUT ;
    USE SIGNAL ;
    ANTENNADIFFAREA 2.673000 ;
    PORT
      LAYER met2 ;
        RECT 36.430 199.720 36.710 200.000 ;
    END
  END wbs_dat_o[2]
  PIN wbs_dat_o[30]
    DIRECTION OUTPUT ;
    USE SIGNAL ;
    PORT
      LAYER met2 ;
        RECT 155.110 199.720 155.390 200.000 ;
    END
  END wbs_dat_o[30]
  PIN wbs_dat_o[31]
    DIRECTION OUTPUT ;
    USE SIGNAL ;
    PORT
      LAYER met2 ;
        RECT 159.250 199.720 159.530 200.000 ;
    END
  END wbs_dat_o[31]
  PIN wbs_dat_o[3]
    DIRECTION OUTPUT ;
    USE SIGNAL ;
    ANTENNADIFFAREA 2.673000 ;
    PORT
      LAYER met2 ;
        RECT 41.950 199.720 42.230 200.000 ;
    END
  END wbs_dat_o[3]
  PIN wbs_dat_o[4]
    DIRECTION OUTPUT ;
    USE SIGNAL ;
    ANTENNADIFFAREA 2.673000 ;
    PORT
      LAYER met2 ;
        RECT 47.470 199.720 47.750 200.000 ;
    END
  END wbs_dat_o[4]
  PIN wbs_dat_o[5]
    DIRECTION OUTPUT ;
    USE SIGNAL ;
    ANTENNADIFFAREA 2.673000 ;
    PORT
      LAYER met2 ;
        RECT 51.610 199.720 51.890 200.000 ;
    END
  END wbs_dat_o[5]
  PIN wbs_dat_o[6]
    DIRECTION OUTPUT ;
    USE SIGNAL ;
    ANTENNADIFFAREA 2.673000 ;
    PORT
      LAYER met2 ;
        RECT 55.750 199.720 56.030 200.000 ;
    END
  END wbs_dat_o[6]
  PIN wbs_dat_o[7]
    DIRECTION OUTPUT ;
    USE SIGNAL ;
    ANTENNADIFFAREA 2.673000 ;
    PORT
      LAYER met2 ;
        RECT 59.890 199.720 60.170 200.000 ;
    END
  END wbs_dat_o[7]
  PIN wbs_dat_o[8]
    DIRECTION OUTPUT ;
    USE SIGNAL ;
    ANTENNADIFFAREA 2.673000 ;
    PORT
      LAYER met2 ;
        RECT 64.030 199.720 64.310 200.000 ;
    END
  END wbs_dat_o[8]
  PIN wbs_dat_o[9]
    DIRECTION OUTPUT ;
    USE SIGNAL ;
    ANTENNADIFFAREA 2.673000 ;
    PORT
      LAYER met2 ;
        RECT 68.170 199.720 68.450 200.000 ;
    END
  END wbs_dat_o[9]
  PIN wbs_sel_i[0]
    DIRECTION INPUT ;
    USE SIGNAL ;
    ANTENNAGATEAREA 0.647700 ;
    ANTENNADIFFAREA 0.434700 ;
    PORT
      LAYER met2 ;
        RECT 26.770 199.720 27.050 200.000 ;
    END
  END wbs_sel_i[0]
  PIN wbs_sel_i[1]
    DIRECTION INPUT ;
    USE SIGNAL ;
    ANTENNAGATEAREA 0.647700 ;
    ANTENNADIFFAREA 0.434700 ;
    PORT
      LAYER met2 ;
        RECT 32.290 199.720 32.570 200.000 ;
    END
  END wbs_sel_i[1]
  PIN wbs_sel_i[2]
    DIRECTION INPUT ;
    USE SIGNAL ;
    PORT
      LAYER met2 ;
        RECT 37.810 199.720 38.090 200.000 ;
    END
  END wbs_sel_i[2]
  PIN wbs_sel_i[3]
    DIRECTION INPUT ;
    USE SIGNAL ;
    PORT
      LAYER met2 ;
        RECT 43.330 199.720 43.610 200.000 ;
    END
  END wbs_sel_i[3]
  PIN wbs_stb_i
    DIRECTION INPUT ;
    USE SIGNAL ;
    ANTENNAGATEAREA 0.647700 ;
    ANTENNADIFFAREA 0.434700 ;
    PORT
      LAYER met2 ;
        RECT 19.870 199.720 20.150 200.000 ;
    END
  END wbs_stb_i
  PIN wbs_we_i
    DIRECTION INPUT ;
    USE SIGNAL ;
    ANTENNAGATEAREA 0.647700 ;
    ANTENNADIFFAREA 0.434700 ;
    PORT
      LAYER met2 ;
        RECT 21.250 199.720 21.530 200.000 ;
    END
  END wbs_we_i
  OBS
      LAYER nwell ;
        RECT 5.330 10.795 194.310 187.870 ;
      LAYER li1 ;
        RECT 5.520 10.795 194.120 187.765 ;
      LAYER met1 ;
        RECT 0.990 9.900 196.350 187.920 ;
      LAYER met2 ;
        RECT 1.010 199.440 14.070 199.720 ;
        RECT 14.910 199.440 15.450 199.720 ;
        RECT 16.290 199.440 16.830 199.720 ;
        RECT 17.670 199.440 18.210 199.720 ;
        RECT 19.050 199.440 19.590 199.720 ;
        RECT 20.430 199.440 20.970 199.720 ;
        RECT 21.810 199.440 22.350 199.720 ;
        RECT 23.190 199.440 23.730 199.720 ;
        RECT 24.570 199.440 25.110 199.720 ;
        RECT 25.950 199.440 26.490 199.720 ;
        RECT 27.330 199.440 27.870 199.720 ;
        RECT 28.710 199.440 29.250 199.720 ;
        RECT 30.090 199.440 30.630 199.720 ;
        RECT 31.470 199.440 32.010 199.720 ;
        RECT 32.850 199.440 33.390 199.720 ;
        RECT 34.230 199.440 34.770 199.720 ;
        RECT 35.610 199.440 36.150 199.720 ;
        RECT 36.990 199.440 37.530 199.720 ;
        RECT 38.370 199.440 38.910 199.720 ;
        RECT 39.750 199.440 40.290 199.720 ;
        RECT 41.130 199.440 41.670 199.720 ;
        RECT 42.510 199.440 43.050 199.720 ;
        RECT 43.890 199.440 44.430 199.720 ;
        RECT 45.270 199.440 45.810 199.720 ;
        RECT 46.650 199.440 47.190 199.720 ;
        RECT 48.030 199.440 48.570 199.720 ;
        RECT 49.410 199.440 49.950 199.720 ;
        RECT 50.790 199.440 51.330 199.720 ;
        RECT 52.170 199.440 52.710 199.720 ;
        RECT 53.550 199.440 54.090 199.720 ;
        RECT 54.930 199.440 55.470 199.720 ;
        RECT 56.310 199.440 56.850 199.720 ;
        RECT 57.690 199.440 58.230 199.720 ;
        RECT 59.070 199.440 59.610 199.720 ;
        RECT 60.450 199.440 60.990 199.720 ;
        RECT 61.830 199.440 62.370 199.720 ;
        RECT 63.210 199.440 63.750 199.720 ;
        RECT 64.590 199.440 65.130 199.720 ;
        RECT 65.970 199.440 66.510 199.720 ;
        RECT 67.350 199.440 67.890 199.720 ;
        RECT 68.730 199.440 69.270 199.720 ;
        RECT 70.110 199.440 70.650 199.720 ;
        RECT 71.490 199.440 72.030 199.720 ;
        RECT 72.870 199.440 73.410 199.720 ;
        RECT 74.250 199.440 74.790 199.720 ;
        RECT 75.630 199.440 76.170 199.720 ;
        RECT 77.010 199.440 77.550 199.720 ;
        RECT 78.390 199.440 78.930 199.720 ;
        RECT 79.770 199.440 80.310 199.720 ;
        RECT 81.150 199.440 81.690 199.720 ;
        RECT 82.530 199.440 83.070 199.720 ;
        RECT 83.910 199.440 84.450 199.720 ;
        RECT 85.290 199.440 85.830 199.720 ;
        RECT 86.670 199.440 87.210 199.720 ;
        RECT 88.050 199.440 88.590 199.720 ;
        RECT 89.430 199.440 89.970 199.720 ;
        RECT 90.810 199.440 91.350 199.720 ;
        RECT 92.190 199.440 92.730 199.720 ;
        RECT 93.570 199.440 94.110 199.720 ;
        RECT 94.950 199.440 95.490 199.720 ;
        RECT 96.330 199.440 96.870 199.720 ;
        RECT 97.710 199.440 98.250 199.720 ;
        RECT 99.090 199.440 99.630 199.720 ;
        RECT 100.470 199.440 101.010 199.720 ;
        RECT 101.850 199.440 102.390 199.720 ;
        RECT 103.230 199.440 103.770 199.720 ;
        RECT 104.610 199.440 105.150 199.720 ;
        RECT 105.990 199.440 106.530 199.720 ;
        RECT 107.370 199.440 107.910 199.720 ;
        RECT 108.750 199.440 109.290 199.720 ;
        RECT 110.130 199.440 110.670 199.720 ;
        RECT 111.510 199.440 112.050 199.720 ;
        RECT 112.890 199.440 113.430 199.720 ;
        RECT 114.270 199.440 114.810 199.720 ;
        RECT 115.650 199.440 116.190 199.720 ;
        RECT 117.030 199.440 117.570 199.720 ;
        RECT 118.410 199.440 118.950 199.720 ;
        RECT 119.790 199.440 120.330 199.720 ;
        RECT 121.170 199.440 121.710 199.720 ;
        RECT 122.550 199.440 123.090 199.720 ;
        RECT 123.930 199.440 124.470 199.720 ;
        RECT 125.310 199.440 125.850 199.720 ;
        RECT 126.690 199.440 127.230 199.720 ;
        RECT 128.070 199.440 128.610 199.720 ;
        RECT 129.450 199.440 129.990 199.720 ;
        RECT 130.830 199.440 131.370 199.720 ;
        RECT 132.210 199.440 132.750 199.720 ;
        RECT 133.590 199.440 134.130 199.720 ;
        RECT 134.970 199.440 135.510 199.720 ;
        RECT 136.350 199.440 136.890 199.720 ;
        RECT 137.730 199.440 138.270 199.720 ;
        RECT 139.110 199.440 139.650 199.720 ;
        RECT 140.490 199.440 141.030 199.720 ;
        RECT 141.870 199.440 142.410 199.720 ;
        RECT 143.250 199.440 143.790 199.720 ;
        RECT 144.630 199.440 145.170 199.720 ;
        RECT 146.010 199.440 146.550 199.720 ;
        RECT 147.390 199.440 147.930 199.720 ;
        RECT 148.770 199.440 149.310 199.720 ;
        RECT 150.150 199.440 150.690 199.720 ;
        RECT 151.530 199.440 152.070 199.720 ;
        RECT 152.910 199.440 153.450 199.720 ;
        RECT 154.290 199.440 154.830 199.720 ;
        RECT 155.670 199.440 156.210 199.720 ;
        RECT 157.050 199.440 157.590 199.720 ;
        RECT 158.430 199.440 158.970 199.720 ;
        RECT 159.810 199.440 160.350 199.720 ;
        RECT 161.190 199.440 161.730 199.720 ;
        RECT 162.570 199.440 163.110 199.720 ;
        RECT 163.950 199.440 164.490 199.720 ;
        RECT 165.330 199.440 165.870 199.720 ;
        RECT 166.710 199.440 167.250 199.720 ;
        RECT 168.090 199.440 168.630 199.720 ;
        RECT 169.470 199.440 170.010 199.720 ;
        RECT 170.850 199.440 171.390 199.720 ;
        RECT 172.230 199.440 172.770 199.720 ;
        RECT 173.610 199.440 174.150 199.720 ;
        RECT 174.990 199.440 175.530 199.720 ;
        RECT 176.370 199.440 176.910 199.720 ;
        RECT 177.750 199.440 178.290 199.720 ;
        RECT 179.130 199.440 179.670 199.720 ;
        RECT 180.510 199.440 181.050 199.720 ;
        RECT 181.890 199.440 182.430 199.720 ;
        RECT 183.270 199.440 183.810 199.720 ;
        RECT 184.650 199.440 185.190 199.720 ;
        RECT 186.030 199.440 196.330 199.720 ;
        RECT 1.010 0.560 196.330 199.440 ;
        RECT 1.010 0.070 11.770 0.560 ;
        RECT 12.610 0.070 13.150 0.560 ;
        RECT 13.990 0.070 14.530 0.560 ;
        RECT 15.370 0.070 15.910 0.560 ;
        RECT 16.750 0.070 17.290 0.560 ;
        RECT 18.130 0.070 18.670 0.560 ;
        RECT 19.510 0.070 20.050 0.560 ;
        RECT 20.890 0.070 21.430 0.560 ;
        RECT 22.270 0.070 22.810 0.560 ;
        RECT 23.650 0.070 24.190 0.560 ;
        RECT 25.030 0.070 25.570 0.560 ;
        RECT 26.410 0.070 26.950 0.560 ;
        RECT 27.790 0.070 28.330 0.560 ;
        RECT 29.170 0.070 29.710 0.560 ;
        RECT 30.550 0.070 31.090 0.560 ;
        RECT 31.930 0.070 32.470 0.560 ;
        RECT 33.310 0.070 33.850 0.560 ;
        RECT 34.690 0.070 35.230 0.560 ;
        RECT 36.070 0.070 36.610 0.560 ;
        RECT 37.450 0.070 37.990 0.560 ;
        RECT 38.830 0.070 39.370 0.560 ;
        RECT 40.210 0.070 40.750 0.560 ;
        RECT 41.590 0.070 42.130 0.560 ;
        RECT 42.970 0.070 43.510 0.560 ;
        RECT 44.350 0.070 44.890 0.560 ;
        RECT 45.730 0.070 46.270 0.560 ;
        RECT 47.110 0.070 47.650 0.560 ;
        RECT 48.490 0.070 49.030 0.560 ;
        RECT 49.870 0.070 50.410 0.560 ;
        RECT 51.250 0.070 51.790 0.560 ;
        RECT 52.630 0.070 53.170 0.560 ;
        RECT 54.010 0.070 54.550 0.560 ;
        RECT 55.390 0.070 55.930 0.560 ;
        RECT 56.770 0.070 57.310 0.560 ;
        RECT 58.150 0.070 58.690 0.560 ;
        RECT 59.530 0.070 60.070 0.560 ;
        RECT 60.910 0.070 61.450 0.560 ;
        RECT 62.290 0.070 62.830 0.560 ;
        RECT 63.670 0.070 64.210 0.560 ;
        RECT 65.050 0.070 65.590 0.560 ;
        RECT 66.430 0.070 66.970 0.560 ;
        RECT 67.810 0.070 68.350 0.560 ;
        RECT 69.190 0.070 69.730 0.560 ;
        RECT 70.570 0.070 71.110 0.560 ;
        RECT 71.950 0.070 72.490 0.560 ;
        RECT 73.330 0.070 73.870 0.560 ;
        RECT 74.710 0.070 75.250 0.560 ;
        RECT 76.090 0.070 76.630 0.560 ;
        RECT 77.470 0.070 78.010 0.560 ;
        RECT 78.850 0.070 79.390 0.560 ;
        RECT 80.230 0.070 80.770 0.560 ;
        RECT 81.610 0.070 82.150 0.560 ;
        RECT 82.990 0.070 83.530 0.560 ;
        RECT 84.370 0.070 84.910 0.560 ;
        RECT 85.750 0.070 86.290 0.560 ;
        RECT 87.130 0.070 87.670 0.560 ;
        RECT 88.510 0.070 89.050 0.560 ;
        RECT 89.890 0.070 90.430 0.560 ;
        RECT 91.270 0.070 91.810 0.560 ;
        RECT 92.650 0.070 93.190 0.560 ;
        RECT 94.030 0.070 94.570 0.560 ;
        RECT 95.410 0.070 95.950 0.560 ;
        RECT 96.790 0.070 97.330 0.560 ;
        RECT 98.170 0.070 98.710 0.560 ;
        RECT 99.550 0.070 100.090 0.560 ;
        RECT 100.930 0.070 101.470 0.560 ;
        RECT 102.310 0.070 102.850 0.560 ;
        RECT 103.690 0.070 104.230 0.560 ;
        RECT 105.070 0.070 105.610 0.560 ;
        RECT 106.450 0.070 106.990 0.560 ;
        RECT 107.830 0.070 108.370 0.560 ;
        RECT 109.210 0.070 109.750 0.560 ;
        RECT 110.590 0.070 111.130 0.560 ;
        RECT 111.970 0.070 112.510 0.560 ;
        RECT 113.350 0.070 113.890 0.560 ;
        RECT 114.730 0.070 115.270 0.560 ;
        RECT 116.110 0.070 116.650 0.560 ;
        RECT 117.490 0.070 118.030 0.560 ;
        RECT 118.870 0.070 119.410 0.560 ;
        RECT 120.250 0.070 120.790 0.560 ;
        RECT 121.630 0.070 122.170 0.560 ;
        RECT 123.010 0.070 123.550 0.560 ;
        RECT 124.390 0.070 124.930 0.560 ;
        RECT 125.770 0.070 126.310 0.560 ;
        RECT 127.150 0.070 127.690 0.560 ;
        RECT 128.530 0.070 129.070 0.560 ;
        RECT 129.910 0.070 130.450 0.560 ;
        RECT 131.290 0.070 131.830 0.560 ;
        RECT 132.670 0.070 133.210 0.560 ;
        RECT 134.050 0.070 134.590 0.560 ;
        RECT 135.430 0.070 135.970 0.560 ;
        RECT 136.810 0.070 137.350 0.560 ;
        RECT 138.190 0.070 138.730 0.560 ;
        RECT 139.570 0.070 140.110 0.560 ;
        RECT 140.950 0.070 141.490 0.560 ;
        RECT 142.330 0.070 142.870 0.560 ;
        RECT 143.710 0.070 144.250 0.560 ;
        RECT 145.090 0.070 145.630 0.560 ;
        RECT 146.470 0.070 147.010 0.560 ;
        RECT 147.850 0.070 148.390 0.560 ;
        RECT 149.230 0.070 149.770 0.560 ;
        RECT 150.610 0.070 151.150 0.560 ;
        RECT 151.990 0.070 152.530 0.560 ;
        RECT 153.370 0.070 153.910 0.560 ;
        RECT 154.750 0.070 155.290 0.560 ;
        RECT 156.130 0.070 156.670 0.560 ;
        RECT 157.510 0.070 158.050 0.560 ;
        RECT 158.890 0.070 159.430 0.560 ;
        RECT 160.270 0.070 160.810 0.560 ;
        RECT 161.650 0.070 162.190 0.560 ;
        RECT 163.030 0.070 163.570 0.560 ;
        RECT 164.410 0.070 164.950 0.560 ;
        RECT 165.790 0.070 166.330 0.560 ;
        RECT 167.170 0.070 167.710 0.560 ;
        RECT 168.550 0.070 169.090 0.560 ;
        RECT 169.930 0.070 170.470 0.560 ;
        RECT 171.310 0.070 171.850 0.560 ;
        RECT 172.690 0.070 173.230 0.560 ;
        RECT 174.070 0.070 174.610 0.560 ;
        RECT 175.450 0.070 175.990 0.560 ;
        RECT 176.830 0.070 177.370 0.560 ;
        RECT 178.210 0.070 178.750 0.560 ;
        RECT 179.590 0.070 180.130 0.560 ;
        RECT 180.970 0.070 181.510 0.560 ;
        RECT 182.350 0.070 182.890 0.560 ;
        RECT 183.730 0.070 184.270 0.560 ;
        RECT 185.110 0.070 185.650 0.560 ;
        RECT 186.490 0.070 187.030 0.560 ;
        RECT 187.870 0.070 196.330 0.560 ;
      LAYER met3 ;
        RECT 1.000 1.535 199.000 196.345 ;
      LAYER met4 ;
        RECT 16.855 145.015 20.640 184.785 ;
        RECT 23.040 145.015 23.940 184.785 ;
        RECT 26.340 145.015 30.985 184.785 ;
  END
END user_proj_example
END LIBRARY

